VERSION 5.7 ;
  NOWIREEXTENSIONATPIN ON ;
  DIVIDERCHAR "/" ;
  BUSBITCHARS "[]" ;
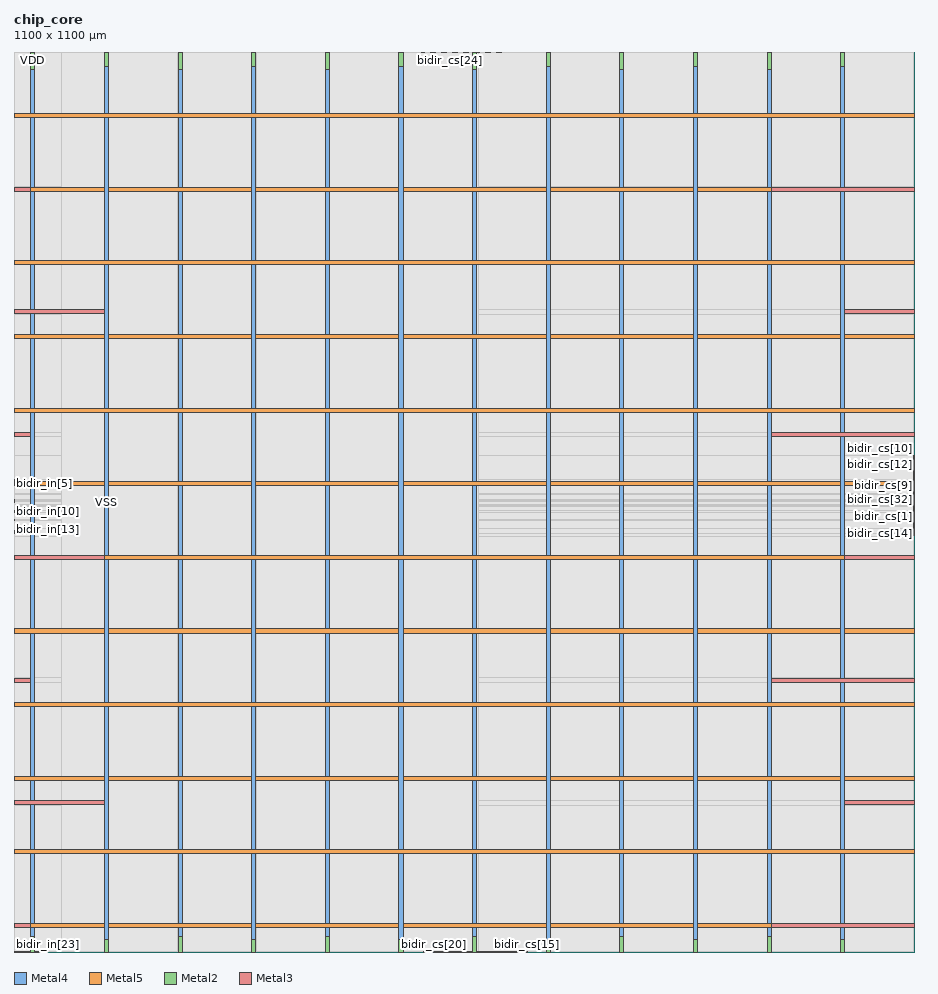
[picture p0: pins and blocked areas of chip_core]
MACRO chip_core
  CLASS BLOCK ;
  FOREIGN chip_core ;
  ORIGIN 0.000 0.000 ;
  SIZE 1100.000 BY 1100.000 ;
  PIN VDD
    DIRECTION INOUT ;
    USE POWER ;
    PORT
      LAYER Metal4 ;
        RECT 20.540 0.000 25.540 1100.000 ;
    END
    PORT
      LAYER Metal4 ;
        RECT 200.540 0.000 205.540 1100.000 ;
    END
    PORT
      LAYER Metal4 ;
        RECT 380.540 0.000 385.540 1100.000 ;
    END
    PORT
      LAYER Metal4 ;
        RECT 560.540 0.000 565.540 1100.000 ;
    END
    PORT
      LAYER Metal4 ;
        RECT 740.540 0.000 745.540 1100.000 ;
    END
    PORT
      LAYER Metal4 ;
        RECT 920.540 0.000 925.540 1100.000 ;
    END
    PORT
      LAYER Metal5 ;
        RECT 0.000 29.830 1100.000 34.830 ;
    END
    PORT
      LAYER Metal5 ;
        RECT 0.000 209.830 1100.000 214.830 ;
    END
    PORT
      LAYER Metal5 ;
        RECT 0.000 389.830 1100.000 394.830 ;
    END
    PORT
      LAYER Metal5 ;
        RECT 0.000 569.830 1100.000 574.830 ;
    END
    PORT
      LAYER Metal5 ;
        RECT 0.000 749.830 1100.000 754.830 ;
    END
    PORT
      LAYER Metal5 ;
        RECT 0.000 929.830 1100.000 934.830 ;
    END
    PORT
      LAYER Metal2 ;
        RECT 20.540 0.000 25.540 19.470 ;
    END
    PORT
      LAYER Metal2 ;
        RECT 20.540 1078.130 25.540 1100.000 ;
    END
    PORT
      LAYER Metal2 ;
        RECT 200.540 0.000 205.540 19.470 ;
    END
    PORT
      LAYER Metal2 ;
        RECT 200.540 1078.130 205.540 1100.000 ;
    END
    PORT
      LAYER Metal2 ;
        RECT 380.540 0.000 385.540 19.470 ;
    END
    PORT
      LAYER Metal2 ;
        RECT 380.540 1078.130 385.540 1100.000 ;
    END
    PORT
      LAYER Metal2 ;
        RECT 560.540 0.000 565.540 19.470 ;
    END
    PORT
      LAYER Metal2 ;
        RECT 560.540 1078.130 565.540 1100.000 ;
    END
    PORT
      LAYER Metal2 ;
        RECT 740.540 0.000 745.540 19.470 ;
    END
    PORT
      LAYER Metal2 ;
        RECT 740.540 1078.130 745.540 1100.000 ;
    END
    PORT
      LAYER Metal2 ;
        RECT 920.540 0.000 925.540 19.470 ;
    END
    PORT
      LAYER Metal2 ;
        RECT 920.540 1078.130 925.540 1100.000 ;
    END
    PORT
      LAYER Metal3 ;
        RECT 0.000 29.830 20.730 34.830 ;
    END
    PORT
      LAYER Metal3 ;
        RECT 925.350 29.830 1100.000 34.830 ;
    END
    PORT
      LAYER Metal3 ;
        RECT 0.000 329.830 20.730 334.830 ;
    END
    PORT
      LAYER Metal3 ;
        RECT 925.350 329.830 1100.000 334.830 ;
    END
    PORT
      LAYER Metal3 ;
        RECT 0.000 629.830 20.730 634.830 ;
    END
    PORT
      LAYER Metal3 ;
        RECT 925.350 629.830 1100.000 634.830 ;
    END
    PORT
      LAYER Metal3 ;
        RECT 0.000 929.830 20.730 934.830 ;
    END
    PORT
      LAYER Metal3 ;
        RECT 925.350 929.830 1100.000 934.830 ;
    END
  END VDD
  PIN VSS
    DIRECTION INOUT ;
    USE GROUND ;
    PORT
      LAYER Metal4 ;
        RECT 110.540 0.000 115.540 1100.000 ;
    END
    PORT
      LAYER Metal4 ;
        RECT 290.540 0.000 295.540 1100.000 ;
    END
    PORT
      LAYER Metal4 ;
        RECT 470.540 0.000 475.540 1100.000 ;
    END
    PORT
      LAYER Metal4 ;
        RECT 650.540 0.000 655.540 1100.000 ;
    END
    PORT
      LAYER Metal4 ;
        RECT 830.540 0.000 835.540 1100.000 ;
    END
    PORT
      LAYER Metal4 ;
        RECT 1010.540 0.000 1015.540 1100.000 ;
    END
    PORT
      LAYER Metal5 ;
        RECT 0.000 119.830 1100.000 124.830 ;
    END
    PORT
      LAYER Metal5 ;
        RECT 0.000 299.830 1100.000 304.830 ;
    END
    PORT
      LAYER Metal5 ;
        RECT 0.000 479.830 1100.000 484.830 ;
    END
    PORT
      LAYER Metal5 ;
        RECT 0.000 659.830 1100.000 664.830 ;
    END
    PORT
      LAYER Metal5 ;
        RECT 0.000 839.830 1100.000 844.830 ;
    END
    PORT
      LAYER Metal5 ;
        RECT 0.000 1019.830 1100.000 1024.830 ;
    END
    PORT
      LAYER Metal2 ;
        RECT 110.540 0.000 115.540 15.550 ;
    END
    PORT
      LAYER Metal2 ;
        RECT 110.540 1082.050 115.540 1100.000 ;
    END
    PORT
      LAYER Metal2 ;
        RECT 290.540 0.000 295.540 15.550 ;
    END
    PORT
      LAYER Metal2 ;
        RECT 290.540 1082.050 295.540 1100.000 ;
    END
    PORT
      LAYER Metal2 ;
        RECT 470.540 0.000 475.540 15.550 ;
    END
    PORT
      LAYER Metal2 ;
        RECT 470.540 1082.050 475.540 1100.000 ;
    END
    PORT
      LAYER Metal2 ;
        RECT 650.540 0.000 655.540 15.550 ;
    END
    PORT
      LAYER Metal2 ;
        RECT 650.540 1082.050 655.540 1100.000 ;
    END
    PORT
      LAYER Metal2 ;
        RECT 830.540 0.000 835.540 15.550 ;
    END
    PORT
      LAYER Metal2 ;
        RECT 830.540 1082.050 835.540 1100.000 ;
    END
    PORT
      LAYER Metal2 ;
        RECT 1010.540 0.000 1015.540 15.550 ;
    END
    PORT
      LAYER Metal2 ;
        RECT 1010.540 1082.050 1015.540 1100.000 ;
    END
    PORT
      LAYER Metal3 ;
        RECT 0.000 179.830 110.730 184.830 ;
    END
    PORT
      LAYER Metal3 ;
        RECT 1015.350 179.830 1100.000 184.830 ;
    END
    PORT
      LAYER Metal3 ;
        RECT 0.000 479.830 110.730 484.830 ;
    END
    PORT
      LAYER Metal3 ;
        RECT 1015.350 479.830 1100.000 484.830 ;
    END
    PORT
      LAYER Metal3 ;
        RECT 0.000 779.830 110.730 784.830 ;
    END
    PORT
      LAYER Metal3 ;
        RECT 1015.350 779.830 1100.000 784.830 ;
    END
  END VSS
  PIN bidir_cs[0]
    DIRECTION OUTPUT ;
    USE SIGNAL ;
    ANTENNADIFFAREA 0.360800 ;
    PORT
      LAYER Metal2 ;
        RECT 505.120 1099.440 505.680 1100.000 ;
    END
  END bidir_cs[0]
  PIN bidir_cs[10]
    DIRECTION OUTPUT ;
    USE SIGNAL ;
    ANTENNADIFFAREA 0.360800 ;
    PORT
      LAYER Metal3 ;
        RECT 1099.440 605.920 1100.000 606.480 ;
    END
  END bidir_cs[10]
  PIN bidir_cs[11]
    DIRECTION OUTPUT ;
    USE SIGNAL ;
    ANTENNADIFFAREA 0.360800 ;
    PORT
      LAYER Metal2 ;
        RECT 524.160 1099.440 524.720 1100.000 ;
    END
  END bidir_cs[11]
  PIN bidir_cs[12]
    DIRECTION OUTPUT ;
    USE SIGNAL ;
    ANTENNADIFFAREA 0.360800 ;
    PORT
      LAYER Metal3 ;
        RECT 1099.440 595.840 1100.000 596.400 ;
    END
  END bidir_cs[12]
  PIN bidir_cs[13]
    DIRECTION OUTPUT ;
    USE SIGNAL ;
    ANTENNADIFFAREA 0.360800 ;
    PORT
      LAYER Metal3 ;
        RECT 1099.440 508.480 1100.000 509.040 ;
    END
  END bidir_cs[13]
  PIN bidir_cs[14]
    DIRECTION OUTPUT ;
    USE SIGNAL ;
    ANTENNADIFFAREA 0.360800 ;
    PORT
      LAYER Metal3 ;
        RECT 1099.440 510.720 1100.000 511.280 ;
    END
  END bidir_cs[14]
  PIN bidir_cs[15]
    DIRECTION OUTPUT ;
    USE SIGNAL ;
    ANTENNADIFFAREA 0.360800 ;
    PORT
      LAYER Metal2 ;
        RECT 627.200 0.000 627.760 0.560 ;
    END
  END bidir_cs[15]
  PIN bidir_cs[16]
    DIRECTION OUTPUT ;
    USE SIGNAL ;
    ANTENNADIFFAREA 0.360800 ;
    PORT
      LAYER Metal2 ;
        RECT 500.640 0.000 501.200 0.560 ;
    END
  END bidir_cs[16]
  PIN bidir_cs[17]
    DIRECTION OUTPUT ;
    USE SIGNAL ;
    ANTENNADIFFAREA 0.360800 ;
    PORT
      LAYER Metal2 ;
        RECT 545.440 0.000 546.000 0.560 ;
    END
  END bidir_cs[17]
  PIN bidir_cs[18]
    DIRECTION OUTPUT ;
    USE SIGNAL ;
    ANTENNADIFFAREA 0.360800 ;
    PORT
      LAYER Metal3 ;
        RECT 1099.440 520.800 1100.000 521.360 ;
    END
  END bidir_cs[18]
  PIN bidir_cs[19]
    DIRECTION OUTPUT ;
    USE SIGNAL ;
    ANTENNADIFFAREA 0.360800 ;
    PORT
      LAYER Metal2 ;
        RECT 553.280 0.000 553.840 0.560 ;
    END
  END bidir_cs[19]
  PIN bidir_cs[1]
    DIRECTION OUTPUT ;
    USE SIGNAL ;
    ANTENNADIFFAREA 0.360800 ;
    PORT
      LAYER Metal3 ;
        RECT 1099.440 532.000 1100.000 532.560 ;
    END
  END bidir_cs[1]
  PIN bidir_cs[20]
    DIRECTION OUTPUT ;
    USE SIGNAL ;
    ANTENNADIFFAREA 0.360800 ;
    PORT
      LAYER Metal2 ;
        RECT 512.960 0.000 513.520 0.560 ;
    END
  END bidir_cs[20]
  PIN bidir_cs[21]
    DIRECTION OUTPUT ;
    USE SIGNAL ;
    ANTENNADIFFAREA 0.360800 ;
    PORT
      LAYER Metal2 ;
        RECT 524.160 0.000 524.720 0.560 ;
    END
  END bidir_cs[21]
  PIN bidir_cs[22]
    DIRECTION OUTPUT ;
    USE SIGNAL ;
    ANTENNADIFFAREA 0.360800 ;
    PORT
      LAYER Metal2 ;
        RECT 614.880 0.000 615.440 0.560 ;
    END
  END bidir_cs[22]
  PIN bidir_cs[23]
    DIRECTION OUTPUT ;
    USE SIGNAL ;
    ANTENNADIFFAREA 0.360800 ;
    PORT
      LAYER Metal2 ;
        RECT 605.920 0.000 606.480 0.560 ;
    END
  END bidir_cs[23]
  PIN bidir_cs[24]
    DIRECTION OUTPUT ;
    USE SIGNAL ;
    ANTENNADIFFAREA 0.360800 ;
    PORT
      LAYER Metal2 ;
        RECT 533.120 1099.440 533.680 1100.000 ;
    END
  END bidir_cs[24]
  PIN bidir_cs[25]
    DIRECTION OUTPUT ;
    USE SIGNAL ;
    ANTENNADIFFAREA 0.360800 ;
    PORT
      LAYER Metal3 ;
        RECT 1099.440 523.040 1100.000 523.600 ;
    END
  END bidir_cs[25]
  PIN bidir_cs[26]
    DIRECTION OUTPUT ;
    USE SIGNAL ;
    ANTENNADIFFAREA 0.360800 ;
    PORT
      LAYER Metal2 ;
        RECT 594.720 1099.440 595.280 1100.000 ;
    END
  END bidir_cs[26]
  PIN bidir_cs[27]
    DIRECTION OUTPUT ;
    USE SIGNAL ;
    ANTENNADIFFAREA 0.360800 ;
    PORT
      LAYER Metal2 ;
        RECT 549.920 1099.440 550.480 1100.000 ;
    END
  END bidir_cs[27]
  PIN bidir_cs[28]
    DIRECTION OUTPUT ;
    USE SIGNAL ;
    ANTENNADIFFAREA 0.360800 ;
    PORT
      LAYER Metal2 ;
        RECT 505.120 0.000 505.680 0.560 ;
    END
  END bidir_cs[28]
  PIN bidir_cs[29]
    DIRECTION OUTPUT ;
    USE SIGNAL ;
    ANTENNADIFFAREA 0.360800 ;
    PORT
      LAYER Metal3 ;
        RECT 1099.440 524.160 1100.000 524.720 ;
    END
  END bidir_cs[29]
  PIN bidir_cs[2]
    DIRECTION OUTPUT ;
    USE SIGNAL ;
    ANTENNADIFFAREA 0.360800 ;
    PORT
      LAYER Metal2 ;
        RECT 518.560 1099.440 519.120 1100.000 ;
    END
  END bidir_cs[2]
  PIN bidir_cs[30]
    DIRECTION OUTPUT ;
    USE SIGNAL ;
    ANTENNADIFFAREA 0.360800 ;
    PORT
      LAYER Metal3 ;
        RECT 1099.440 536.480 1100.000 537.040 ;
    END
  END bidir_cs[30]
  PIN bidir_cs[31]
    DIRECTION OUTPUT ;
    USE SIGNAL ;
    ANTENNADIFFAREA 0.360800 ;
    PORT
      LAYER Metal2 ;
        RECT 558.880 0.000 559.440 0.560 ;
    END
  END bidir_cs[31]
  PIN bidir_cs[32]
    DIRECTION OUTPUT ;
    USE SIGNAL ;
    ANTENNADIFFAREA 0.360800 ;
    PORT
      LAYER Metal3 ;
        RECT 1099.440 543.200 1100.000 543.760 ;
    END
  END bidir_cs[32]
  PIN bidir_cs[33]
    DIRECTION OUTPUT ;
    USE SIGNAL ;
    ANTENNADIFFAREA 0.360800 ;
    PORT
      LAYER Metal2 ;
        RECT 604.800 0.000 605.360 0.560 ;
    END
  END bidir_cs[33]
  PIN bidir_cs[34]
    DIRECTION OUTPUT ;
    USE SIGNAL ;
    ANTENNADIFFAREA 0.360800 ;
    PORT
      LAYER Metal2 ;
        RECT 570.080 1099.440 570.640 1100.000 ;
    END
  END bidir_cs[34]
  PIN bidir_cs[35]
    DIRECTION OUTPUT ;
    USE SIGNAL ;
    ANTENNADIFFAREA 0.360800 ;
    PORT
      LAYER Metal2 ;
        RECT 519.680 1099.440 520.240 1100.000 ;
    END
  END bidir_cs[35]
  PIN bidir_cs[36]
    DIRECTION OUTPUT ;
    USE SIGNAL ;
    ANTENNADIFFAREA 0.360800 ;
    PORT
      LAYER Metal3 ;
        RECT 1099.440 539.840 1100.000 540.400 ;
    END
  END bidir_cs[36]
  PIN bidir_cs[37]
    DIRECTION OUTPUT ;
    USE SIGNAL ;
    ANTENNADIFFAREA 0.360800 ;
    PORT
      LAYER Metal2 ;
        RECT 532.000 0.000 532.560 0.560 ;
    END
  END bidir_cs[37]
  PIN bidir_cs[38]
    DIRECTION OUTPUT ;
    USE SIGNAL ;
    ANTENNADIFFAREA 0.360800 ;
    PORT
      LAYER Metal2 ;
        RECT 571.200 0.000 571.760 0.560 ;
    END
  END bidir_cs[38]
  PIN bidir_cs[39]
    DIRECTION OUTPUT ;
    USE SIGNAL ;
    ANTENNADIFFAREA 0.360800 ;
    PORT
      LAYER Metal2 ;
        RECT 515.200 0.000 515.760 0.560 ;
    END
  END bidir_cs[39]
  PIN bidir_cs[3]
    DIRECTION OUTPUT ;
    USE SIGNAL ;
    ANTENNADIFFAREA 0.360800 ;
    PORT
      LAYER Metal3 ;
        RECT 1099.440 545.440 1100.000 546.000 ;
    END
  END bidir_cs[3]
  PIN bidir_cs[4]
    DIRECTION OUTPUT ;
    USE SIGNAL ;
    ANTENNADIFFAREA 0.360800 ;
    PORT
      LAYER Metal2 ;
        RECT 548.800 1099.440 549.360 1100.000 ;
    END
  END bidir_cs[4]
  PIN bidir_cs[5]
    DIRECTION OUTPUT ;
    USE SIGNAL ;
    ANTENNADIFFAREA 0.360800 ;
    PORT
      LAYER Metal2 ;
        RECT 590.240 1099.440 590.800 1100.000 ;
    END
  END bidir_cs[5]
  PIN bidir_cs[6]
    DIRECTION OUTPUT ;
    USE SIGNAL ;
    ANTENNADIFFAREA 0.360800 ;
    PORT
      LAYER Metal2 ;
        RECT 508.480 1099.440 509.040 1100.000 ;
    END
  END bidir_cs[6]
  PIN bidir_cs[7]
    DIRECTION OUTPUT ;
    USE SIGNAL ;
    ANTENNADIFFAREA 0.360800 ;
    PORT
      LAYER Metal3 ;
        RECT 1099.440 601.440 1100.000 602.000 ;
    END
  END bidir_cs[7]
  PIN bidir_cs[8]
    DIRECTION OUTPUT ;
    USE SIGNAL ;
    ANTENNADIFFAREA 0.360800 ;
    PORT
      LAYER Metal3 ;
        RECT 1099.440 526.400 1100.000 526.960 ;
    END
  END bidir_cs[8]
  PIN bidir_cs[9]
    DIRECTION OUTPUT ;
    USE SIGNAL ;
    ANTENNADIFFAREA 0.360800 ;
    PORT
      LAYER Metal3 ;
        RECT 1099.440 570.080 1100.000 570.640 ;
    END
  END bidir_cs[9]
  PIN bidir_ie[0]
    DIRECTION OUTPUT ;
    USE SIGNAL ;
    ANTENNADIFFAREA 0.360800 ;
    PORT
      LAYER Metal3 ;
        RECT 1099.440 527.520 1100.000 528.080 ;
    END
  END bidir_ie[0]
  PIN bidir_ie[10]
    DIRECTION OUTPUT ;
    USE SIGNAL ;
    ANTENNADIFFAREA 0.360800 ;
    PORT
      LAYER Metal3 ;
        RECT 1099.440 512.960 1100.000 513.520 ;
    END
  END bidir_ie[10]
  PIN bidir_ie[11]
    DIRECTION OUTPUT ;
    USE SIGNAL ;
    ANTENNADIFFAREA 0.360800 ;
    PORT
      LAYER Metal3 ;
        RECT 1099.440 546.560 1100.000 547.120 ;
    END
  END bidir_ie[11]
  PIN bidir_ie[12]
    DIRECTION OUTPUT ;
    USE SIGNAL ;
    ANTENNADIFFAREA 0.360800 ;
    PORT
      LAYER Metal3 ;
        RECT 1099.440 573.440 1100.000 574.000 ;
    END
  END bidir_ie[12]
  PIN bidir_ie[13]
    DIRECTION OUTPUT ;
    USE SIGNAL ;
    ANTENNADIFFAREA 0.360800 ;
    PORT
      LAYER Metal2 ;
        RECT 588.000 0.000 588.560 0.560 ;
    END
  END bidir_ie[13]
  PIN bidir_ie[14]
    DIRECTION OUTPUT ;
    USE SIGNAL ;
    ANTENNADIFFAREA 0.360800 ;
    PORT
      LAYER Metal3 ;
        RECT 1099.440 557.760 1100.000 558.320 ;
    END
  END bidir_ie[14]
  PIN bidir_ie[15]
    DIRECTION OUTPUT ;
    USE SIGNAL ;
    ANTENNADIFFAREA 0.360800 ;
    PORT
      LAYER Metal3 ;
        RECT 1099.440 592.480 1100.000 593.040 ;
    END
  END bidir_ie[15]
  PIN bidir_ie[16]
    DIRECTION OUTPUT ;
    USE SIGNAL ;
    ANTENNADIFFAREA 0.360800 ;
    PORT
      LAYER Metal2 ;
        RECT 624.960 0.000 625.520 0.560 ;
    END
  END bidir_ie[16]
  PIN bidir_ie[17]
    DIRECTION OUTPUT ;
    USE SIGNAL ;
    ANTENNADIFFAREA 0.360800 ;
    PORT
      LAYER Metal2 ;
        RECT 584.640 1099.440 585.200 1100.000 ;
    END
  END bidir_ie[17]
  PIN bidir_ie[18]
    DIRECTION OUTPUT ;
    USE SIGNAL ;
    ANTENNADIFFAREA 0.360800 ;
    PORT
      LAYER Metal2 ;
        RECT 511.840 1099.440 512.400 1100.000 ;
    END
  END bidir_ie[18]
  PIN bidir_ie[19]
    DIRECTION OUTPUT ;
    USE SIGNAL ;
    ANTENNADIFFAREA 0.360800 ;
    PORT
      LAYER Metal2 ;
        RECT 552.160 1099.440 552.720 1100.000 ;
    END
  END bidir_ie[19]
  PIN bidir_ie[1]
    DIRECTION OUTPUT ;
    USE SIGNAL ;
    ANTENNADIFFAREA 0.360800 ;
    PORT
      LAYER Metal3 ;
        RECT 1099.440 533.120 1100.000 533.680 ;
    END
  END bidir_ie[1]
  PIN bidir_ie[20]
    DIRECTION OUTPUT ;
    USE SIGNAL ;
    ANTENNADIFFAREA 0.360800 ;
    PORT
      LAYER Metal2 ;
        RECT 518.560 0.000 519.120 0.560 ;
    END
  END bidir_ie[20]
  PIN bidir_ie[21]
    DIRECTION OUTPUT ;
    USE SIGNAL ;
    ANTENNADIFFAREA 0.360800 ;
    PORT
      LAYER Metal2 ;
        RECT 499.520 1099.440 500.080 1100.000 ;
    END
  END bidir_ie[21]
  PIN bidir_ie[22]
    DIRECTION OUTPUT ;
    USE SIGNAL ;
    ANTENNADIFFAREA 0.360800 ;
    PORT
      LAYER Metal2 ;
        RECT 547.680 0.000 548.240 0.560 ;
    END
  END bidir_ie[22]
  PIN bidir_ie[23]
    DIRECTION OUTPUT ;
    USE SIGNAL ;
    ANTENNADIFFAREA 0.360800 ;
    PORT
      LAYER Metal3 ;
        RECT 1099.440 521.920 1100.000 522.480 ;
    END
  END bidir_ie[23]
  PIN bidir_ie[24]
    DIRECTION OUTPUT ;
    USE SIGNAL ;
    ANTENNADIFFAREA 0.360800 ;
    PORT
      LAYER Metal2 ;
        RECT 543.200 1099.440 543.760 1100.000 ;
    END
  END bidir_ie[24]
  PIN bidir_ie[25]
    DIRECTION OUTPUT ;
    USE SIGNAL ;
    ANTENNADIFFAREA 0.360800 ;
    PORT
      LAYER Metal2 ;
        RECT 493.920 1099.440 494.480 1100.000 ;
    END
  END bidir_ie[25]
  PIN bidir_ie[26]
    DIRECTION OUTPUT ;
    USE SIGNAL ;
    ANTENNADIFFAREA 0.360800 ;
    PORT
      LAYER Metal2 ;
        RECT 542.080 1099.440 542.640 1100.000 ;
    END
  END bidir_ie[26]
  PIN bidir_ie[27]
    DIRECTION OUTPUT ;
    USE SIGNAL ;
    ANTENNADIFFAREA 0.360800 ;
    PORT
      LAYER Metal2 ;
        RECT 539.840 1099.440 540.400 1100.000 ;
    END
  END bidir_ie[27]
  PIN bidir_ie[28]
    DIRECTION OUTPUT ;
    USE SIGNAL ;
    ANTENNADIFFAREA 0.360800 ;
    PORT
      LAYER Metal2 ;
        RECT 523.040 1099.440 523.600 1100.000 ;
    END
  END bidir_ie[28]
  PIN bidir_ie[29]
    DIRECTION OUTPUT ;
    USE SIGNAL ;
    ANTENNADIFFAREA 0.360800 ;
    PORT
      LAYER Metal2 ;
        RECT 523.040 0.000 523.600 0.560 ;
    END
  END bidir_ie[29]
  PIN bidir_ie[2]
    DIRECTION OUTPUT ;
    USE SIGNAL ;
    ANTENNADIFFAREA 0.360800 ;
    PORT
      LAYER Metal3 ;
        RECT 0.000 549.920 0.560 550.480 ;
    END
  END bidir_ie[2]
  PIN bidir_ie[30]
    DIRECTION OUTPUT ;
    USE SIGNAL ;
    ANTENNADIFFAREA 0.360800 ;
    PORT
      LAYER Metal2 ;
        RECT 556.640 0.000 557.200 0.560 ;
    END
  END bidir_ie[30]
  PIN bidir_ie[31]
    DIRECTION OUTPUT ;
    USE SIGNAL ;
    ANTENNADIFFAREA 0.360800 ;
    PORT
      LAYER Metal3 ;
        RECT 1099.440 553.280 1100.000 553.840 ;
    END
  END bidir_ie[31]
  PIN bidir_ie[32]
    DIRECTION OUTPUT ;
    USE SIGNAL ;
    ANTENNADIFFAREA 0.360800 ;
    PORT
      LAYER Metal3 ;
        RECT 1099.440 596.960 1100.000 597.520 ;
    END
  END bidir_ie[32]
  PIN bidir_ie[33]
    DIRECTION OUTPUT ;
    USE SIGNAL ;
    ANTENNADIFFAREA 0.360800 ;
    PORT
      LAYER Metal2 ;
        RECT 547.680 1099.440 548.240 1100.000 ;
    END
  END bidir_ie[33]
  PIN bidir_ie[34]
    DIRECTION OUTPUT ;
    USE SIGNAL ;
    ANTENNADIFFAREA 0.360800 ;
    PORT
      LAYER Metal2 ;
        RECT 556.640 1099.440 557.200 1100.000 ;
    END
  END bidir_ie[34]
  PIN bidir_ie[35]
    DIRECTION OUTPUT ;
    USE SIGNAL ;
    ANTENNADIFFAREA 0.360800 ;
    PORT
      LAYER Metal3 ;
        RECT 1099.440 554.400 1100.000 554.960 ;
    END
  END bidir_ie[35]
  PIN bidir_ie[36]
    DIRECTION OUTPUT ;
    USE SIGNAL ;
    ANTENNADIFFAREA 0.360800 ;
    PORT
      LAYER Metal2 ;
        RECT 551.040 0.000 551.600 0.560 ;
    END
  END bidir_ie[36]
  PIN bidir_ie[37]
    DIRECTION OUTPUT ;
    USE SIGNAL ;
    ANTENNADIFFAREA 0.360800 ;
    PORT
      LAYER Metal2 ;
        RECT 552.160 0.000 552.720 0.560 ;
    END
  END bidir_ie[37]
  PIN bidir_ie[38]
    DIRECTION OUTPUT ;
    USE SIGNAL ;
    ANTENNADIFFAREA 0.360800 ;
    PORT
      LAYER Metal2 ;
        RECT 584.640 0.000 585.200 0.560 ;
    END
  END bidir_ie[38]
  PIN bidir_ie[39]
    DIRECTION OUTPUT ;
    USE SIGNAL ;
    ANTENNADIFFAREA 0.360800 ;
    PORT
      LAYER Metal3 ;
        RECT 1099.440 511.840 1100.000 512.400 ;
    END
  END bidir_ie[39]
  PIN bidir_ie[3]
    DIRECTION OUTPUT ;
    USE SIGNAL ;
    ANTENNADIFFAREA 0.360800 ;
    PORT
      LAYER Metal2 ;
        RECT 618.240 0.000 618.800 0.560 ;
    END
  END bidir_ie[3]
  PIN bidir_ie[4]
    DIRECTION OUTPUT ;
    USE SIGNAL ;
    ANTENNADIFFAREA 0.360800 ;
    PORT
      LAYER Metal2 ;
        RECT 526.400 0.000 526.960 0.560 ;
    END
  END bidir_ie[4]
  PIN bidir_ie[5]
    DIRECTION OUTPUT ;
    USE SIGNAL ;
    ANTENNADIFFAREA 0.360800 ;
    PORT
      LAYER Metal2 ;
        RECT 608.160 0.000 608.720 0.560 ;
    END
  END bidir_ie[5]
  PIN bidir_ie[6]
    DIRECTION OUTPUT ;
    USE SIGNAL ;
    ANTENNADIFFAREA 0.360800 ;
    PORT
      LAYER Metal2 ;
        RECT 512.960 1099.440 513.520 1100.000 ;
    END
  END bidir_ie[6]
  PIN bidir_ie[7]
    DIRECTION OUTPUT ;
    USE SIGNAL ;
    ANTENNADIFFAREA 0.360800 ;
    PORT
      LAYER Metal3 ;
        RECT 0.000 548.800 0.560 549.360 ;
    END
  END bidir_ie[7]
  PIN bidir_ie[8]
    DIRECTION OUTPUT ;
    USE SIGNAL ;
    ANTENNADIFFAREA 0.360800 ;
    PORT
      LAYER Metal2 ;
        RECT 591.360 0.000 591.920 0.560 ;
    END
  END bidir_ie[8]
  PIN bidir_ie[9]
    DIRECTION OUTPUT ;
    USE SIGNAL ;
    ANTENNADIFFAREA 0.360800 ;
    PORT
      LAYER Metal2 ;
        RECT 567.840 0.000 568.400 0.560 ;
    END
  END bidir_ie[9]
  PIN bidir_in[0]
    DIRECTION INPUT ;
    USE SIGNAL ;
    ANTENNAGATEAREA 0.396000 ;
    ANTENNADIFFAREA 0.410400 ;
    PORT
      LAYER Metal3 ;
        RECT 0.000 575.680 0.560 576.240 ;
    END
  END bidir_in[0]
  PIN bidir_in[10]
    DIRECTION INPUT ;
    USE SIGNAL ;
    ANTENNAGATEAREA 0.396000 ;
    ANTENNADIFFAREA 0.410400 ;
    PORT
      LAYER Metal3 ;
        RECT 0.000 537.600 0.560 538.160 ;
    END
  END bidir_in[10]
  PIN bidir_in[11]
    DIRECTION INPUT ;
    USE SIGNAL ;
    ANTENNAGATEAREA 0.396000 ;
    ANTENNADIFFAREA 0.410400 ;
    PORT
      LAYER Metal3 ;
        RECT 0.000 538.720 0.560 539.280 ;
    END
  END bidir_in[11]
  PIN bidir_in[12]
    DIRECTION INPUT ;
    USE SIGNAL ;
    ANTENNAGATEAREA 0.396000 ;
    ANTENNADIFFAREA 0.410400 ;
    PORT
      LAYER Metal3 ;
        RECT 0.000 544.320 0.560 544.880 ;
    END
  END bidir_in[12]
  PIN bidir_in[13]
    DIRECTION INPUT ;
    USE SIGNAL ;
    ANTENNAGATEAREA 0.396000 ;
    ANTENNADIFFAREA 0.410400 ;
    PORT
      LAYER Metal3 ;
        RECT 0.000 516.320 0.560 516.880 ;
    END
  END bidir_in[13]
  PIN bidir_in[14]
    DIRECTION INPUT ;
    USE SIGNAL ;
    ANTENNAGATEAREA 0.396000 ;
    ANTENNADIFFAREA 0.410400 ;
    PORT
      LAYER Metal3 ;
        RECT 0.000 552.160 0.560 552.720 ;
    END
  END bidir_in[14]
  PIN bidir_in[15]
    DIRECTION INPUT ;
    USE SIGNAL ;
    ANTENNAGATEAREA 0.396000 ;
    ANTENNADIFFAREA 0.410400 ;
    PORT
      LAYER Metal3 ;
        RECT 0.000 527.520 0.560 528.080 ;
    END
  END bidir_in[15]
  PIN bidir_in[16]
    DIRECTION INPUT ;
    USE SIGNAL ;
    PORT
      LAYER Metal2 ;
        RECT 1.120 0.000 1.680 0.560 ;
    END
  END bidir_in[16]
  PIN bidir_in[17]
    DIRECTION INPUT ;
    USE SIGNAL ;
    PORT
      LAYER Metal2 ;
        RECT 2.240 0.000 2.800 0.560 ;
    END
  END bidir_in[17]
  PIN bidir_in[18]
    DIRECTION INPUT ;
    USE SIGNAL ;
    PORT
      LAYER Metal2 ;
        RECT 3.360 0.000 3.920 0.560 ;
    END
  END bidir_in[18]
  PIN bidir_in[19]
    DIRECTION INPUT ;
    USE SIGNAL ;
    PORT
      LAYER Metal2 ;
        RECT 4.480 0.000 5.040 0.560 ;
    END
  END bidir_in[19]
  PIN bidir_in[1]
    DIRECTION INPUT ;
    USE SIGNAL ;
    ANTENNAGATEAREA 0.396000 ;
    ANTENNADIFFAREA 0.410400 ;
    PORT
      LAYER Metal3 ;
        RECT 0.000 511.840 0.560 512.400 ;
    END
  END bidir_in[1]
  PIN bidir_in[20]
    DIRECTION INPUT ;
    USE SIGNAL ;
    PORT
      LAYER Metal2 ;
        RECT 5.600 0.000 6.160 0.560 ;
    END
  END bidir_in[20]
  PIN bidir_in[21]
    DIRECTION INPUT ;
    USE SIGNAL ;
    PORT
      LAYER Metal2 ;
        RECT 6.720 0.000 7.280 0.560 ;
    END
  END bidir_in[21]
  PIN bidir_in[22]
    DIRECTION INPUT ;
    USE SIGNAL ;
    PORT
      LAYER Metal2 ;
        RECT 7.840 0.000 8.400 0.560 ;
    END
  END bidir_in[22]
  PIN bidir_in[23]
    DIRECTION INPUT ;
    USE SIGNAL ;
    PORT
      LAYER Metal2 ;
        RECT 8.960 0.000 9.520 0.560 ;
    END
  END bidir_in[23]
  PIN bidir_in[24]
    DIRECTION INPUT ;
    USE SIGNAL ;
    PORT
      LAYER Metal2 ;
        RECT 10.080 0.000 10.640 0.560 ;
    END
  END bidir_in[24]
  PIN bidir_in[25]
    DIRECTION INPUT ;
    USE SIGNAL ;
    PORT
      LAYER Metal2 ;
        RECT 11.200 0.000 11.760 0.560 ;
    END
  END bidir_in[25]
  PIN bidir_in[26]
    DIRECTION INPUT ;
    USE SIGNAL ;
    PORT
      LAYER Metal2 ;
        RECT 12.320 0.000 12.880 0.560 ;
    END
  END bidir_in[26]
  PIN bidir_in[27]
    DIRECTION INPUT ;
    USE SIGNAL ;
    PORT
      LAYER Metal2 ;
        RECT 13.440 0.000 14.000 0.560 ;
    END
  END bidir_in[27]
  PIN bidir_in[28]
    DIRECTION INPUT ;
    USE SIGNAL ;
    PORT
      LAYER Metal2 ;
        RECT 14.560 0.000 15.120 0.560 ;
    END
  END bidir_in[28]
  PIN bidir_in[29]
    DIRECTION INPUT ;
    USE SIGNAL ;
    PORT
      LAYER Metal2 ;
        RECT 15.680 0.000 16.240 0.560 ;
    END
  END bidir_in[29]
  PIN bidir_in[2]
    DIRECTION INPUT ;
    USE SIGNAL ;
    ANTENNAGATEAREA 0.396000 ;
    ANTENNADIFFAREA 0.410400 ;
    PORT
      LAYER Metal3 ;
        RECT 0.000 574.560 0.560 575.120 ;
    END
  END bidir_in[2]
  PIN bidir_in[30]
    DIRECTION INPUT ;
    USE SIGNAL ;
    PORT
      LAYER Metal2 ;
        RECT 16.800 0.000 17.360 0.560 ;
    END
  END bidir_in[30]
  PIN bidir_in[31]
    DIRECTION INPUT ;
    USE SIGNAL ;
    PORT
      LAYER Metal2 ;
        RECT 17.920 0.000 18.480 0.560 ;
    END
  END bidir_in[31]
  PIN bidir_in[32]
    DIRECTION INPUT ;
    USE SIGNAL ;
    PORT
      LAYER Metal2 ;
        RECT 19.040 0.000 19.600 0.560 ;
    END
  END bidir_in[32]
  PIN bidir_in[33]
    DIRECTION INPUT ;
    USE SIGNAL ;
    PORT
      LAYER Metal2 ;
        RECT 20.160 0.000 20.720 0.560 ;
    END
  END bidir_in[33]
  PIN bidir_in[34]
    DIRECTION INPUT ;
    USE SIGNAL ;
    PORT
      LAYER Metal2 ;
        RECT 25.760 0.000 26.320 0.560 ;
    END
  END bidir_in[34]
  PIN bidir_in[35]
    DIRECTION INPUT ;
    USE SIGNAL ;
    PORT
      LAYER Metal2 ;
        RECT 26.880 0.000 27.440 0.560 ;
    END
  END bidir_in[35]
  PIN bidir_in[36]
    DIRECTION INPUT ;
    USE SIGNAL ;
    PORT
      LAYER Metal2 ;
        RECT 28.000 0.000 28.560 0.560 ;
    END
  END bidir_in[36]
  PIN bidir_in[37]
    DIRECTION INPUT ;
    USE SIGNAL ;
    PORT
      LAYER Metal2 ;
        RECT 29.120 0.000 29.680 0.560 ;
    END
  END bidir_in[37]
  PIN bidir_in[38]
    DIRECTION INPUT ;
    USE SIGNAL ;
    PORT
      LAYER Metal2 ;
        RECT 30.240 0.000 30.800 0.560 ;
    END
  END bidir_in[38]
  PIN bidir_in[39]
    DIRECTION INPUT ;
    USE SIGNAL ;
    PORT
      LAYER Metal2 ;
        RECT 31.360 0.000 31.920 0.560 ;
    END
  END bidir_in[39]
  PIN bidir_in[3]
    DIRECTION INPUT ;
    USE SIGNAL ;
    ANTENNAGATEAREA 0.396000 ;
    ANTENNADIFFAREA 0.410400 ;
    PORT
      LAYER Metal3 ;
        RECT 0.000 558.880 0.560 559.440 ;
    END
  END bidir_in[3]
  PIN bidir_in[4]
    DIRECTION INPUT ;
    USE SIGNAL ;
    ANTENNAGATEAREA 0.396000 ;
    ANTENNADIFFAREA 0.410400 ;
    PORT
      LAYER Metal3 ;
        RECT 0.000 515.200 0.560 515.760 ;
    END
  END bidir_in[4]
  PIN bidir_in[5]
    DIRECTION INPUT ;
    USE SIGNAL ;
    ANTENNAGATEAREA 0.396000 ;
    ANTENNADIFFAREA 0.410400 ;
    PORT
      LAYER Metal3 ;
        RECT 0.000 572.320 0.560 572.880 ;
    END
  END bidir_in[5]
  PIN bidir_in[6]
    DIRECTION INPUT ;
    USE SIGNAL ;
    ANTENNAGATEAREA 0.396000 ;
    ANTENNADIFFAREA 0.410400 ;
    PORT
      LAYER Metal3 ;
        RECT 0.000 512.960 0.560 513.520 ;
    END
  END bidir_in[6]
  PIN bidir_in[7]
    DIRECTION INPUT ;
    USE SIGNAL ;
    ANTENNAGATEAREA 0.396000 ;
    ANTENNADIFFAREA 0.410400 ;
    PORT
      LAYER Metal3 ;
        RECT 0.000 573.440 0.560 574.000 ;
    END
  END bidir_in[7]
  PIN bidir_in[8]
    DIRECTION INPUT ;
    USE SIGNAL ;
    ANTENNAGATEAREA 0.396000 ;
    ANTENNADIFFAREA 0.410400 ;
    PORT
      LAYER Metal3 ;
        RECT 0.000 514.080 0.560 514.640 ;
    END
  END bidir_in[8]
  PIN bidir_in[9]
    DIRECTION INPUT ;
    USE SIGNAL ;
    ANTENNAGATEAREA 0.396000 ;
    ANTENNADIFFAREA 0.410400 ;
    PORT
      LAYER Metal3 ;
        RECT 0.000 560.000 0.560 560.560 ;
    END
  END bidir_in[9]
  PIN bidir_oe[0]
    DIRECTION OUTPUT ;
    USE SIGNAL ;
    ANTENNADIFFAREA 0.360800 ;
    PORT
      LAYER Metal2 ;
        RECT 546.560 0.000 547.120 0.560 ;
    END
  END bidir_oe[0]
  PIN bidir_oe[10]
    DIRECTION OUTPUT ;
    USE SIGNAL ;
    ANTENNADIFFAREA 0.360800 ;
    PORT
      LAYER Metal2 ;
        RECT 517.440 1099.440 518.000 1100.000 ;
    END
  END bidir_oe[10]
  PIN bidir_oe[11]
    DIRECTION OUTPUT ;
    USE SIGNAL ;
    ANTENNADIFFAREA 0.360800 ;
    PORT
      LAYER Metal2 ;
        RECT 533.120 0.000 533.680 0.560 ;
    END
  END bidir_oe[11]
  PIN bidir_oe[12]
    DIRECTION OUTPUT ;
    USE SIGNAL ;
    ANTENNADIFFAREA 0.360800 ;
    PORT
      LAYER Metal3 ;
        RECT 1099.440 537.600 1100.000 538.160 ;
    END
  END bidir_oe[12]
  PIN bidir_oe[13]
    DIRECTION OUTPUT ;
    USE SIGNAL ;
    ANTENNADIFFAREA 0.360800 ;
    PORT
      LAYER Metal2 ;
        RECT 570.080 0.000 570.640 0.560 ;
    END
  END bidir_oe[13]
  PIN bidir_oe[14]
    DIRECTION OUTPUT ;
    USE SIGNAL ;
    ANTENNADIFFAREA 0.360800 ;
    PORT
      LAYER Metal2 ;
        RECT 544.320 1099.440 544.880 1100.000 ;
    END
  END bidir_oe[14]
  PIN bidir_oe[15]
    DIRECTION OUTPUT ;
    USE SIGNAL ;
    ANTENNADIFFAREA 0.360800 ;
    PORT
      LAYER Metal3 ;
        RECT 1099.440 562.240 1100.000 562.800 ;
    END
  END bidir_oe[15]
  PIN bidir_oe[16]
    DIRECTION OUTPUT ;
    USE SIGNAL ;
    ANTENNADIFFAREA 0.536800 ;
    PORT
      LAYER Metal3 ;
        RECT 1099.440 519.680 1100.000 520.240 ;
    END
  END bidir_oe[16]
  PIN bidir_oe[17]
    DIRECTION OUTPUT ;
    USE SIGNAL ;
    ANTENNADIFFAREA 0.536800 ;
    PORT
      LAYER Metal3 ;
        RECT 1099.440 565.600 1100.000 566.160 ;
    END
  END bidir_oe[17]
  PIN bidir_oe[18]
    DIRECTION OUTPUT ;
    USE SIGNAL ;
    ANTENNADIFFAREA 0.536800 ;
    PORT
      LAYER Metal2 ;
        RECT 600.320 0.000 600.880 0.560 ;
    END
  END bidir_oe[18]
  PIN bidir_oe[19]
    DIRECTION OUTPUT ;
    USE SIGNAL ;
    ANTENNADIFFAREA 0.536800 ;
    PORT
      LAYER Metal2 ;
        RECT 594.720 0.000 595.280 0.560 ;
    END
  END bidir_oe[19]
  PIN bidir_oe[1]
    DIRECTION OUTPUT ;
    USE SIGNAL ;
    ANTENNADIFFAREA 0.360800 ;
    PORT
      LAYER Metal3 ;
        RECT 1099.440 572.320 1100.000 572.880 ;
    END
  END bidir_oe[1]
  PIN bidir_oe[20]
    DIRECTION OUTPUT ;
    USE SIGNAL ;
    ANTENNADIFFAREA 0.536800 ;
    PORT
      LAYER Metal2 ;
        RECT 520.800 0.000 521.360 0.560 ;
    END
  END bidir_oe[20]
  PIN bidir_oe[21]
    DIRECTION OUTPUT ;
    USE SIGNAL ;
    ANTENNADIFFAREA 0.536800 ;
    PORT
      LAYER Metal2 ;
        RECT 530.880 1099.440 531.440 1100.000 ;
    END
  END bidir_oe[21]
  PIN bidir_oe[22]
    DIRECTION OUTPUT ;
    USE SIGNAL ;
    ANTENNADIFFAREA 0.536800 ;
    PORT
      LAYER Metal2 ;
        RECT 536.480 0.000 537.040 0.560 ;
    END
  END bidir_oe[22]
  PIN bidir_oe[23]
    DIRECTION OUTPUT ;
    USE SIGNAL ;
    ANTENNADIFFAREA 0.536800 ;
    PORT
      LAYER Metal3 ;
        RECT 1099.440 564.480 1100.000 565.040 ;
    END
  END bidir_oe[23]
  PIN bidir_oe[24]
    DIRECTION OUTPUT ;
    USE SIGNAL ;
    ANTENNADIFFAREA 0.536800 ;
    PORT
      LAYER Metal2 ;
        RECT 509.600 0.000 510.160 0.560 ;
    END
  END bidir_oe[24]
  PIN bidir_oe[25]
    DIRECTION OUTPUT ;
    USE SIGNAL ;
    ANTENNADIFFAREA 0.536800 ;
    PORT
      LAYER Metal2 ;
        RECT 592.480 1099.440 593.040 1100.000 ;
    END
  END bidir_oe[25]
  PIN bidir_oe[26]
    DIRECTION OUTPUT ;
    USE SIGNAL ;
    ANTENNADIFFAREA 0.536800 ;
    PORT
      LAYER Metal2 ;
        RECT 511.840 0.000 512.400 0.560 ;
    END
  END bidir_oe[26]
  PIN bidir_oe[27]
    DIRECTION OUTPUT ;
    USE SIGNAL ;
    ANTENNADIFFAREA 0.536800 ;
    PORT
      LAYER Metal2 ;
        RECT 514.080 0.000 514.640 0.560 ;
    END
  END bidir_oe[27]
  PIN bidir_oe[28]
    DIRECTION OUTPUT ;
    USE SIGNAL ;
    ANTENNADIFFAREA 0.536800 ;
    PORT
      LAYER Metal2 ;
        RECT 582.400 0.000 582.960 0.560 ;
    END
  END bidir_oe[28]
  PIN bidir_oe[29]
    DIRECTION OUTPUT ;
    USE SIGNAL ;
    ANTENNADIFFAREA 0.536800 ;
    PORT
      LAYER Metal2 ;
        RECT 585.760 1099.440 586.320 1100.000 ;
    END
  END bidir_oe[29]
  PIN bidir_oe[2]
    DIRECTION OUTPUT ;
    USE SIGNAL ;
    ANTENNADIFFAREA 0.360800 ;
    PORT
      LAYER Metal3 ;
        RECT 1099.440 540.960 1100.000 541.520 ;
    END
  END bidir_oe[2]
  PIN bidir_oe[30]
    DIRECTION OUTPUT ;
    USE SIGNAL ;
    ANTENNADIFFAREA 0.536800 ;
    PORT
      LAYER Metal2 ;
        RECT 576.800 1099.440 577.360 1100.000 ;
    END
  END bidir_oe[30]
  PIN bidir_oe[31]
    DIRECTION OUTPUT ;
    USE SIGNAL ;
    ANTENNADIFFAREA 0.536800 ;
    PORT
      LAYER Metal2 ;
        RECT 510.720 1099.440 511.280 1100.000 ;
    END
  END bidir_oe[31]
  PIN bidir_oe[32]
    DIRECTION OUTPUT ;
    USE SIGNAL ;
    ANTENNADIFFAREA 0.536800 ;
    PORT
      LAYER Metal2 ;
        RECT 506.240 0.000 506.800 0.560 ;
    END
  END bidir_oe[32]
  PIN bidir_oe[33]
    DIRECTION OUTPUT ;
    USE SIGNAL ;
    ANTENNADIFFAREA 0.536800 ;
    PORT
      LAYER Metal2 ;
        RECT 554.400 0.000 554.960 0.560 ;
    END
  END bidir_oe[33]
  PIN bidir_oe[34]
    DIRECTION OUTPUT ;
    USE SIGNAL ;
    ANTENNADIFFAREA 0.536800 ;
    PORT
      LAYER Metal2 ;
        RECT 530.880 0.000 531.440 0.560 ;
    END
  END bidir_oe[34]
  PIN bidir_oe[35]
    DIRECTION OUTPUT ;
    USE SIGNAL ;
    ANTENNADIFFAREA 0.536800 ;
    PORT
      LAYER Metal2 ;
        RECT 575.680 0.000 576.240 0.560 ;
    END
  END bidir_oe[35]
  PIN bidir_oe[36]
    DIRECTION OUTPUT ;
    USE SIGNAL ;
    ANTENNADIFFAREA 0.536800 ;
    PORT
      LAYER Metal2 ;
        RECT 498.400 1099.440 498.960 1100.000 ;
    END
  END bidir_oe[36]
  PIN bidir_oe[37]
    DIRECTION OUTPUT ;
    USE SIGNAL ;
    ANTENNADIFFAREA 0.536800 ;
    PORT
      LAYER Metal2 ;
        RECT 577.920 1099.440 578.480 1100.000 ;
    END
  END bidir_oe[37]
  PIN bidir_oe[38]
    DIRECTION OUTPUT ;
    USE SIGNAL ;
    ANTENNADIFFAREA 0.536800 ;
    PORT
      LAYER Metal2 ;
        RECT 508.480 0.000 509.040 0.560 ;
    END
  END bidir_oe[38]
  PIN bidir_oe[39]
    DIRECTION OUTPUT ;
    USE SIGNAL ;
    ANTENNADIFFAREA 0.536800 ;
    PORT
      LAYER Metal2 ;
        RECT 527.520 0.000 528.080 0.560 ;
    END
  END bidir_oe[39]
  PIN bidir_oe[3]
    DIRECTION OUTPUT ;
    USE SIGNAL ;
    ANTENNADIFFAREA 0.360800 ;
    PORT
      LAYER Metal2 ;
        RECT 613.760 0.000 614.320 0.560 ;
    END
  END bidir_oe[3]
  PIN bidir_oe[4]
    DIRECTION OUTPUT ;
    USE SIGNAL ;
    ANTENNADIFFAREA 0.360800 ;
    PORT
      LAYER Metal2 ;
        RECT 581.280 0.000 581.840 0.560 ;
    END
  END bidir_oe[4]
  PIN bidir_oe[5]
    DIRECTION OUTPUT ;
    USE SIGNAL ;
    ANTENNADIFFAREA 0.360800 ;
    PORT
      LAYER Metal2 ;
        RECT 507.360 0.000 507.920 0.560 ;
    END
  END bidir_oe[5]
  PIN bidir_oe[6]
    DIRECTION OUTPUT ;
    USE SIGNAL ;
    ANTENNADIFFAREA 0.360800 ;
    PORT
      LAYER Metal2 ;
        RECT 538.720 1099.440 539.280 1100.000 ;
    END
  END bidir_oe[6]
  PIN bidir_oe[7]
    DIRECTION OUTPUT ;
    USE SIGNAL ;
    ANTENNADIFFAREA 0.360800 ;
    PORT
      LAYER Metal2 ;
        RECT 580.160 1099.440 580.720 1100.000 ;
    END
  END bidir_oe[7]
  PIN bidir_oe[8]
    DIRECTION OUTPUT ;
    USE SIGNAL ;
    ANTENNADIFFAREA 0.360800 ;
    PORT
      LAYER Metal2 ;
        RECT 535.360 0.000 535.920 0.560 ;
    END
  END bidir_oe[8]
  PIN bidir_oe[9]
    DIRECTION OUTPUT ;
    USE SIGNAL ;
    ANTENNADIFFAREA 0.360800 ;
    PORT
      LAYER Metal3 ;
        RECT 1099.440 571.200 1100.000 571.760 ;
    END
  END bidir_oe[9]
  PIN bidir_out[0]
    DIRECTION OUTPUT ;
    USE SIGNAL ;
    ANTENNADIFFAREA 0.360800 ;
    PORT
      LAYER Metal2 ;
        RECT 589.120 1099.440 589.680 1100.000 ;
    END
  END bidir_out[0]
  PIN bidir_out[10]
    DIRECTION OUTPUT ;
    USE SIGNAL ;
    ANTENNADIFFAREA 0.360800 ;
    PORT
      LAYER Metal2 ;
        RECT 565.600 1099.440 566.160 1100.000 ;
    END
  END bidir_out[10]
  PIN bidir_out[11]
    DIRECTION OUTPUT ;
    USE SIGNAL ;
    ANTENNADIFFAREA 0.360800 ;
    PORT
      LAYER Metal3 ;
        RECT 1099.440 555.520 1100.000 556.080 ;
    END
  END bidir_out[11]
  PIN bidir_out[12]
    DIRECTION OUTPUT ;
    USE SIGNAL ;
    ANTENNADIFFAREA 0.360800 ;
    PORT
      LAYER Metal2 ;
        RECT 540.960 0.000 541.520 0.560 ;
    END
  END bidir_out[12]
  PIN bidir_out[13]
    DIRECTION OUTPUT ;
    USE SIGNAL ;
    ANTENNADIFFAREA 0.360800 ;
    PORT
      LAYER Metal2 ;
        RECT 555.520 1099.440 556.080 1100.000 ;
    END
  END bidir_out[13]
  PIN bidir_out[14]
    DIRECTION OUTPUT ;
    USE SIGNAL ;
    ANTENNADIFFAREA 0.360800 ;
    PORT
      LAYER Metal3 ;
        RECT 1099.440 529.760 1100.000 530.320 ;
    END
  END bidir_out[14]
  PIN bidir_out[15]
    DIRECTION OUTPUT ;
    USE SIGNAL ;
    ANTENNADIFFAREA 0.360800 ;
    PORT
      LAYER Metal2 ;
        RECT 551.040 1099.440 551.600 1100.000 ;
    END
  END bidir_out[15]
  PIN bidir_out[16]
    DIRECTION OUTPUT ;
    USE SIGNAL ;
    ANTENNADIFFAREA 0.536800 ;
    PORT
      LAYER Metal3 ;
        RECT 1099.440 581.280 1100.000 581.840 ;
    END
  END bidir_out[16]
  PIN bidir_out[17]
    DIRECTION OUTPUT ;
    USE SIGNAL ;
    ANTENNADIFFAREA 0.360800 ;
    PORT
      LAYER Metal2 ;
        RECT 576.800 0.000 577.360 0.560 ;
    END
  END bidir_out[17]
  PIN bidir_out[18]
    DIRECTION OUTPUT ;
    USE SIGNAL ;
    ANTENNADIFFAREA 0.360800 ;
    PORT
      LAYER Metal3 ;
        RECT 1099.440 534.240 1100.000 534.800 ;
    END
  END bidir_out[18]
  PIN bidir_out[19]
    DIRECTION OUTPUT ;
    USE SIGNAL ;
    ANTENNADIFFAREA 0.360800 ;
    PORT
      LAYER Metal2 ;
        RECT 539.840 0.000 540.400 0.560 ;
    END
  END bidir_out[19]
  PIN bidir_out[1]
    DIRECTION OUTPUT ;
    USE SIGNAL ;
    ANTENNADIFFAREA 0.360800 ;
    PORT
      LAYER Metal2 ;
        RECT 566.720 1099.440 567.280 1100.000 ;
    END
  END bidir_out[1]
  PIN bidir_out[20]
    DIRECTION OUTPUT ;
    USE SIGNAL ;
    ANTENNADIFFAREA 0.360800 ;
    PORT
      LAYER Metal2 ;
        RECT 554.400 1099.440 554.960 1100.000 ;
    END
  END bidir_out[20]
  PIN bidir_out[21]
    DIRECTION OUTPUT ;
    USE SIGNAL ;
    ANTENNADIFFAREA 0.360800 ;
    PORT
      LAYER Metal2 ;
        RECT 535.360 1099.440 535.920 1100.000 ;
    END
  END bidir_out[21]
  PIN bidir_out[22]
    DIRECTION OUTPUT ;
    USE SIGNAL ;
    ANTENNADIFFAREA 0.360800 ;
    PORT
      LAYER Metal2 ;
        RECT 593.600 1099.440 594.160 1100.000 ;
    END
  END bidir_out[22]
  PIN bidir_out[23]
    DIRECTION OUTPUT ;
    USE SIGNAL ;
    ANTENNADIFFAREA 0.360800 ;
    PORT
      LAYER Metal3 ;
        RECT 1099.440 547.680 1100.000 548.240 ;
    END
  END bidir_out[23]
  PIN bidir_out[24]
    DIRECTION OUTPUT ;
    USE SIGNAL ;
    ANTENNADIFFAREA 0.360800 ;
    PORT
      LAYER Metal2 ;
        RECT 540.960 1099.440 541.520 1100.000 ;
    END
  END bidir_out[24]
  PIN bidir_out[25]
    DIRECTION OUTPUT ;
    USE SIGNAL ;
    ANTENNADIFFAREA 0.360800 ;
    PORT
      LAYER Metal2 ;
        RECT 521.920 0.000 522.480 0.560 ;
    END
  END bidir_out[25]
  PIN bidir_out[26]
    DIRECTION OUTPUT ;
    USE SIGNAL ;
    ANTENNADIFFAREA 0.360800 ;
    PORT
      LAYER Metal3 ;
        RECT 1099.440 600.320 1100.000 600.880 ;
    END
  END bidir_out[26]
  PIN bidir_out[27]
    DIRECTION OUTPUT ;
    USE SIGNAL ;
    ANTENNADIFFAREA 0.360800 ;
    PORT
      LAYER Metal2 ;
        RECT 616.000 0.000 616.560 0.560 ;
    END
  END bidir_out[27]
  PIN bidir_out[28]
    DIRECTION OUTPUT ;
    USE SIGNAL ;
    ANTENNADIFFAREA 0.360800 ;
    PORT
      LAYER Metal2 ;
        RECT 517.440 0.000 518.000 0.560 ;
    END
  END bidir_out[28]
  PIN bidir_out[29]
    DIRECTION OUTPUT ;
    USE SIGNAL ;
    ANTENNADIFFAREA 0.360800 ;
    PORT
      LAYER Metal2 ;
        RECT 537.600 1099.440 538.160 1100.000 ;
    END
  END bidir_out[29]
  PIN bidir_out[2]
    DIRECTION OUTPUT ;
    USE SIGNAL ;
    ANTENNADIFFAREA 0.360800 ;
    PORT
      LAYER Metal2 ;
        RECT 507.360 1099.440 507.920 1100.000 ;
    END
  END bidir_out[2]
  PIN bidir_out[30]
    DIRECTION OUTPUT ;
    USE SIGNAL ;
    ANTENNADIFFAREA 0.360800 ;
    PORT
      LAYER Metal3 ;
        RECT 0.000 547.680 0.560 548.240 ;
    END
  END bidir_out[30]
  PIN bidir_out[31]
    DIRECTION OUTPUT ;
    USE SIGNAL ;
    ANTENNADIFFAREA 0.360800 ;
    PORT
      LAYER Metal3 ;
        RECT 1099.440 509.600 1100.000 510.160 ;
    END
  END bidir_out[31]
  PIN bidir_out[32]
    DIRECTION OUTPUT ;
    USE SIGNAL ;
    ANTENNADIFFAREA 0.360800 ;
    PORT
      LAYER Metal2 ;
        RECT 585.760 0.000 586.320 0.560 ;
    END
  END bidir_out[32]
  PIN bidir_out[33]
    DIRECTION OUTPUT ;
    USE SIGNAL ;
    ANTENNADIFFAREA 0.360800 ;
    PORT
      LAYER Metal2 ;
        RECT 619.360 0.000 619.920 0.560 ;
    END
  END bidir_out[33]
  PIN bidir_out[34]
    DIRECTION OUTPUT ;
    USE SIGNAL ;
    ANTENNADIFFAREA 0.360800 ;
    PORT
      LAYER Metal3 ;
        RECT 1099.440 590.240 1100.000 590.800 ;
    END
  END bidir_out[34]
  PIN bidir_out[35]
    DIRECTION OUTPUT ;
    USE SIGNAL ;
    ANTENNADIFFAREA 0.360800 ;
    PORT
      LAYER Metal2 ;
        RECT 621.600 0.000 622.160 0.560 ;
    END
  END bidir_out[35]
  PIN bidir_out[36]
    DIRECTION OUTPUT ;
    USE SIGNAL ;
    ANTENNADIFFAREA 0.360800 ;
    PORT
      LAYER Metal2 ;
        RECT 596.960 0.000 597.520 0.560 ;
    END
  END bidir_out[36]
  PIN bidir_out[37]
    DIRECTION OUTPUT ;
    USE SIGNAL ;
    ANTENNADIFFAREA 0.360800 ;
    PORT
      LAYER Metal2 ;
        RECT 492.800 1099.440 493.360 1100.000 ;
    END
  END bidir_out[37]
  PIN bidir_out[38]
    DIRECTION OUTPUT ;
    USE SIGNAL ;
    ANTENNADIFFAREA 0.360800 ;
    PORT
      LAYER Metal3 ;
        RECT 1099.440 552.160 1100.000 552.720 ;
    END
  END bidir_out[38]
  PIN bidir_out[39]
    DIRECTION OUTPUT ;
    USE SIGNAL ;
    ANTENNADIFFAREA 0.360800 ;
    PORT
      LAYER Metal3 ;
        RECT 1099.440 579.040 1100.000 579.600 ;
    END
  END bidir_out[39]
  PIN bidir_out[3]
    DIRECTION OUTPUT ;
    USE SIGNAL ;
    ANTENNADIFFAREA 0.360800 ;
    PORT
      LAYER Metal2 ;
        RECT 620.480 0.000 621.040 0.560 ;
    END
  END bidir_out[3]
  PIN bidir_out[4]
    DIRECTION OUTPUT ;
    USE SIGNAL ;
    ANTENNADIFFAREA 0.360800 ;
    PORT
      LAYER Metal3 ;
        RECT 1099.440 551.040 1100.000 551.600 ;
    END
  END bidir_out[4]
  PIN bidir_out[5]
    DIRECTION OUTPUT ;
    USE SIGNAL ;
    ANTENNADIFFAREA 0.360800 ;
    PORT
      LAYER Metal2 ;
        RECT 601.440 0.000 602.000 0.560 ;
    END
  END bidir_out[5]
  PIN bidir_out[6]
    DIRECTION OUTPUT ;
    USE SIGNAL ;
    ANTENNADIFFAREA 0.360800 ;
    PORT
      LAYER Metal3 ;
        RECT 1099.440 594.720 1100.000 595.280 ;
    END
  END bidir_out[6]
  PIN bidir_out[7]
    DIRECTION OUTPUT ;
    USE SIGNAL ;
    ANTENNADIFFAREA 0.360800 ;
    PORT
      LAYER Metal2 ;
        RECT 586.880 1099.440 587.440 1100.000 ;
    END
  END bidir_out[7]
  PIN bidir_out[8]
    DIRECTION OUTPUT ;
    USE SIGNAL ;
    ANTENNADIFFAREA 0.360800 ;
    PORT
      LAYER Metal3 ;
        RECT 1099.440 517.440 1100.000 518.000 ;
    END
  END bidir_out[8]
  PIN bidir_out[9]
    DIRECTION OUTPUT ;
    USE SIGNAL ;
    ANTENNADIFFAREA 0.360800 ;
    PORT
      LAYER Metal3 ;
        RECT 1099.440 560.000 1100.000 560.560 ;
    END
  END bidir_out[9]
  PIN bidir_pd[0]
    DIRECTION OUTPUT ;
    USE SIGNAL ;
    ANTENNADIFFAREA 0.360800 ;
    PORT
      LAYER Metal2 ;
        RECT 572.320 1099.440 572.880 1100.000 ;
    END
  END bidir_pd[0]
  PIN bidir_pd[10]
    DIRECTION OUTPUT ;
    USE SIGNAL ;
    ANTENNADIFFAREA 0.360800 ;
    PORT
      LAYER Metal2 ;
        RECT 565.600 0.000 566.160 0.560 ;
    END
  END bidir_pd[10]
  PIN bidir_pd[11]
    DIRECTION OUTPUT ;
    USE SIGNAL ;
    ANTENNADIFFAREA 0.360800 ;
    PORT
      LAYER Metal3 ;
        RECT 1099.440 566.720 1100.000 567.280 ;
    END
  END bidir_pd[11]
  PIN bidir_pd[12]
    DIRECTION OUTPUT ;
    USE SIGNAL ;
    ANTENNADIFFAREA 0.360800 ;
    PORT
      LAYER Metal3 ;
        RECT 1099.440 576.800 1100.000 577.360 ;
    END
  END bidir_pd[12]
  PIN bidir_pd[13]
    DIRECTION OUTPUT ;
    USE SIGNAL ;
    ANTENNADIFFAREA 0.360800 ;
    PORT
      LAYER Metal3 ;
        RECT 1099.440 591.360 1100.000 591.920 ;
    END
  END bidir_pd[13]
  PIN bidir_pd[14]
    DIRECTION OUTPUT ;
    USE SIGNAL ;
    ANTENNADIFFAREA 0.360800 ;
    PORT
      LAYER Metal2 ;
        RECT 599.200 0.000 599.760 0.560 ;
    END
  END bidir_pd[14]
  PIN bidir_pd[15]
    DIRECTION OUTPUT ;
    USE SIGNAL ;
    ANTENNADIFFAREA 0.360800 ;
    PORT
      LAYER Metal3 ;
        RECT 1099.440 604.800 1100.000 605.360 ;
    END
  END bidir_pd[15]
  PIN bidir_pd[16]
    DIRECTION OUTPUT ;
    USE SIGNAL ;
    ANTENNADIFFAREA 0.360800 ;
    PORT
      LAYER Metal2 ;
        RECT 504.000 0.000 504.560 0.560 ;
    END
  END bidir_pd[16]
  PIN bidir_pd[17]
    DIRECTION OUTPUT ;
    USE SIGNAL ;
    ANTENNADIFFAREA 0.360800 ;
    PORT
      LAYER Metal2 ;
        RECT 549.920 0.000 550.480 0.560 ;
    END
  END bidir_pd[17]
  PIN bidir_pd[18]
    DIRECTION OUTPUT ;
    USE SIGNAL ;
    ANTENNADIFFAREA 0.360800 ;
    PORT
      LAYER Metal3 ;
        RECT 1099.440 549.920 1100.000 550.480 ;
    END
  END bidir_pd[18]
  PIN bidir_pd[19]
    DIRECTION OUTPUT ;
    USE SIGNAL ;
    ANTENNADIFFAREA 0.360800 ;
    PORT
      LAYER Metal3 ;
        RECT 1099.440 602.560 1100.000 603.120 ;
    END
  END bidir_pd[19]
  PIN bidir_pd[1]
    DIRECTION OUTPUT ;
    USE SIGNAL ;
    ANTENNADIFFAREA 0.360800 ;
    PORT
      LAYER Metal2 ;
        RECT 583.520 1099.440 584.080 1100.000 ;
    END
  END bidir_pd[1]
  PIN bidir_pd[20]
    DIRECTION OUTPUT ;
    USE SIGNAL ;
    ANTENNADIFFAREA 0.360800 ;
    PORT
      LAYER Metal2 ;
        RECT 528.640 0.000 529.200 0.560 ;
    END
  END bidir_pd[20]
  PIN bidir_pd[21]
    DIRECTION OUTPUT ;
    USE SIGNAL ;
    ANTENNADIFFAREA 0.360800 ;
    PORT
      LAYER Metal2 ;
        RECT 543.200 0.000 543.760 0.560 ;
    END
  END bidir_pd[21]
  PIN bidir_pd[22]
    DIRECTION OUTPUT ;
    USE SIGNAL ;
    ANTENNADIFFAREA 0.360800 ;
    PORT
      LAYER Metal2 ;
        RECT 602.560 0.000 603.120 0.560 ;
    END
  END bidir_pd[22]
  PIN bidir_pd[23]
    DIRECTION OUTPUT ;
    USE SIGNAL ;
    ANTENNADIFFAREA 0.360800 ;
    PORT
      LAYER Metal3 ;
        RECT 1099.440 516.320 1100.000 516.880 ;
    END
  END bidir_pd[23]
  PIN bidir_pd[24]
    DIRECTION OUTPUT ;
    USE SIGNAL ;
    ANTENNADIFFAREA 0.360800 ;
    PORT
      LAYER Metal2 ;
        RECT 581.280 1099.440 581.840 1100.000 ;
    END
  END bidir_pd[24]
  PIN bidir_pd[25]
    DIRECTION OUTPUT ;
    USE SIGNAL ;
    ANTENNADIFFAREA 0.360800 ;
    PORT
      LAYER Metal2 ;
        RECT 590.240 0.000 590.800 0.560 ;
    END
  END bidir_pd[25]
  PIN bidir_pd[26]
    DIRECTION OUTPUT ;
    USE SIGNAL ;
    ANTENNADIFFAREA 0.360800 ;
    PORT
      LAYER Metal2 ;
        RECT 520.800 1099.440 521.360 1100.000 ;
    END
  END bidir_pd[26]
  PIN bidir_pd[27]
    DIRECTION OUTPUT ;
    USE SIGNAL ;
    ANTENNADIFFAREA 0.360800 ;
    PORT
      LAYER Metal2 ;
        RECT 510.720 0.000 511.280 0.560 ;
    END
  END bidir_pd[27]
  PIN bidir_pd[28]
    DIRECTION OUTPUT ;
    USE SIGNAL ;
    ANTENNADIFFAREA 0.360800 ;
    PORT
      LAYER Metal2 ;
        RECT 572.320 0.000 572.880 0.560 ;
    END
  END bidir_pd[28]
  PIN bidir_pd[29]
    DIRECTION OUTPUT ;
    USE SIGNAL ;
    ANTENNADIFFAREA 0.360800 ;
    PORT
      LAYER Metal2 ;
        RECT 501.760 0.000 502.320 0.560 ;
    END
  END bidir_pd[29]
  PIN bidir_pd[2]
    DIRECTION OUTPUT ;
    USE SIGNAL ;
    ANTENNADIFFAREA 0.360800 ;
    PORT
      LAYER Metal2 ;
        RECT 558.880 1099.440 559.440 1100.000 ;
    END
  END bidir_pd[2]
  PIN bidir_pd[30]
    DIRECTION OUTPUT ;
    USE SIGNAL ;
    ANTENNADIFFAREA 0.360800 ;
    PORT
      LAYER Metal2 ;
        RECT 548.800 0.000 549.360 0.560 ;
    END
  END bidir_pd[30]
  PIN bidir_pd[31]
    DIRECTION OUTPUT ;
    USE SIGNAL ;
    ANTENNADIFFAREA 0.360800 ;
    PORT
      LAYER Metal2 ;
        RECT 527.520 1099.440 528.080 1100.000 ;
    END
  END bidir_pd[31]
  PIN bidir_pd[32]
    DIRECTION OUTPUT ;
    USE SIGNAL ;
    ANTENNADIFFAREA 0.360800 ;
    PORT
      LAYER Metal3 ;
        RECT 1099.440 514.080 1100.000 514.640 ;
    END
  END bidir_pd[32]
  PIN bidir_pd[33]
    DIRECTION OUTPUT ;
    USE SIGNAL ;
    ANTENNADIFFAREA 0.360800 ;
    PORT
      LAYER Metal2 ;
        RECT 537.600 0.000 538.160 0.560 ;
    END
  END bidir_pd[33]
  PIN bidir_pd[34]
    DIRECTION OUTPUT ;
    USE SIGNAL ;
    ANTENNADIFFAREA 0.360800 ;
    PORT
      LAYER Metal3 ;
        RECT 1099.440 585.760 1100.000 586.320 ;
    END
  END bidir_pd[34]
  PIN bidir_pd[35]
    DIRECTION OUTPUT ;
    USE SIGNAL ;
    ANTENNADIFFAREA 0.360800 ;
    PORT
      LAYER Metal3 ;
        RECT 1099.440 598.080 1100.000 598.640 ;
    END
  END bidir_pd[35]
  PIN bidir_pd[36]
    DIRECTION OUTPUT ;
    USE SIGNAL ;
    ANTENNADIFFAREA 0.360800 ;
    PORT
      LAYER Metal2 ;
        RECT 516.320 0.000 516.880 0.560 ;
    END
  END bidir_pd[36]
  PIN bidir_pd[37]
    DIRECTION OUTPUT ;
    USE SIGNAL ;
    ANTENNADIFFAREA 0.360800 ;
    PORT
      LAYER Metal2 ;
        RECT 516.320 1099.440 516.880 1100.000 ;
    END
  END bidir_pd[37]
  PIN bidir_pd[38]
    DIRECTION OUTPUT ;
    USE SIGNAL ;
    ANTENNADIFFAREA 0.360800 ;
    PORT
      LAYER Metal2 ;
        RECT 622.720 0.000 623.280 0.560 ;
    END
  END bidir_pd[38]
  PIN bidir_pd[39]
    DIRECTION OUTPUT ;
    USE SIGNAL ;
    ANTENNADIFFAREA 0.360800 ;
    PORT
      LAYER Metal3 ;
        RECT 1099.440 544.320 1100.000 544.880 ;
    END
  END bidir_pd[39]
  PIN bidir_pd[3]
    DIRECTION OUTPUT ;
    USE SIGNAL ;
    ANTENNADIFFAREA 0.360800 ;
    PORT
      LAYER Metal2 ;
        RECT 573.440 1099.440 574.000 1100.000 ;
    END
  END bidir_pd[3]
  PIN bidir_pd[4]
    DIRECTION OUTPUT ;
    USE SIGNAL ;
    ANTENNADIFFAREA 0.360800 ;
    PORT
      LAYER Metal2 ;
        RECT 575.680 1099.440 576.240 1100.000 ;
    END
  END bidir_pd[4]
  PIN bidir_pd[5]
    DIRECTION OUTPUT ;
    USE SIGNAL ;
    ANTENNADIFFAREA 0.360800 ;
    PORT
      LAYER Metal2 ;
        RECT 532.000 1099.440 532.560 1100.000 ;
    END
  END bidir_pd[5]
  PIN bidir_pd[6]
    DIRECTION OUTPUT ;
    USE SIGNAL ;
    ANTENNADIFFAREA 0.360800 ;
    PORT
      LAYER Metal2 ;
        RECT 521.920 1099.440 522.480 1100.000 ;
    END
  END bidir_pd[6]
  PIN bidir_pd[7]
    DIRECTION OUTPUT ;
    USE SIGNAL ;
    ANTENNADIFFAREA 0.360800 ;
    PORT
      LAYER Metal3 ;
        RECT 1099.440 558.880 1100.000 559.440 ;
    END
  END bidir_pd[7]
  PIN bidir_pd[8]
    DIRECTION OUTPUT ;
    USE SIGNAL ;
    ANTENNADIFFAREA 0.360800 ;
    PORT
      LAYER Metal2 ;
        RECT 502.880 0.000 503.440 0.560 ;
    END
  END bidir_pd[8]
  PIN bidir_pd[9]
    DIRECTION OUTPUT ;
    USE SIGNAL ;
    ANTENNADIFFAREA 0.360800 ;
    PORT
      LAYER Metal2 ;
        RECT 573.440 0.000 574.000 0.560 ;
    END
  END bidir_pd[9]
  PIN bidir_pu[0]
    DIRECTION OUTPUT ;
    USE SIGNAL ;
    ANTENNADIFFAREA 0.360800 ;
    PORT
      LAYER Metal2 ;
        RECT 574.560 1099.440 575.120 1100.000 ;
    END
  END bidir_pu[0]
  PIN bidir_pu[10]
    DIRECTION OUTPUT ;
    USE SIGNAL ;
    ANTENNADIFFAREA 0.360800 ;
    PORT
      LAYER Metal2 ;
        RECT 519.680 0.000 520.240 0.560 ;
    END
  END bidir_pu[10]
  PIN bidir_pu[11]
    DIRECTION OUTPUT ;
    USE SIGNAL ;
    ANTENNADIFFAREA 0.360800 ;
    PORT
      LAYER Metal2 ;
        RECT 612.640 0.000 613.200 0.560 ;
    END
  END bidir_pu[11]
  PIN bidir_pu[12]
    DIRECTION OUTPUT ;
    USE SIGNAL ;
    ANTENNADIFFAREA 0.360800 ;
    PORT
      LAYER Metal3 ;
        RECT 1099.440 556.640 1100.000 557.200 ;
    END
  END bidir_pu[12]
  PIN bidir_pu[13]
    DIRECTION OUTPUT ;
    USE SIGNAL ;
    ANTENNADIFFAREA 0.360800 ;
    PORT
      LAYER Metal3 ;
        RECT 1099.440 575.680 1100.000 576.240 ;
    END
  END bidir_pu[13]
  PIN bidir_pu[14]
    DIRECTION OUTPUT ;
    USE SIGNAL ;
    ANTENNADIFFAREA 0.360800 ;
    PORT
      LAYER Metal2 ;
        RECT 567.840 1099.440 568.400 1100.000 ;
    END
  END bidir_pu[14]
  PIN bidir_pu[15]
    DIRECTION OUTPUT ;
    USE SIGNAL ;
    ANTENNADIFFAREA 0.360800 ;
    PORT
      LAYER Metal2 ;
        RECT 626.080 0.000 626.640 0.560 ;
    END
  END bidir_pu[15]
  PIN bidir_pu[16]
    DIRECTION OUTPUT ;
    USE SIGNAL ;
    ANTENNADIFFAREA 0.360800 ;
    PORT
      LAYER Metal2 ;
        RECT 593.600 0.000 594.160 0.560 ;
    END
  END bidir_pu[16]
  PIN bidir_pu[17]
    DIRECTION OUTPUT ;
    USE SIGNAL ;
    ANTENNADIFFAREA 0.360800 ;
    PORT
      LAYER Metal2 ;
        RECT 589.120 0.000 589.680 0.560 ;
    END
  END bidir_pu[17]
  PIN bidir_pu[18]
    DIRECTION OUTPUT ;
    USE SIGNAL ;
    ANTENNADIFFAREA 0.360800 ;
    PORT
      LAYER Metal2 ;
        RECT 529.760 0.000 530.320 0.560 ;
    END
  END bidir_pu[18]
  PIN bidir_pu[19]
    DIRECTION OUTPUT ;
    USE SIGNAL ;
    ANTENNADIFFAREA 0.360800 ;
    PORT
      LAYER Metal3 ;
        RECT 1099.440 542.080 1100.000 542.640 ;
    END
  END bidir_pu[19]
  PIN bidir_pu[1]
    DIRECTION OUTPUT ;
    USE SIGNAL ;
    ANTENNADIFFAREA 0.360800 ;
    PORT
      LAYER Metal3 ;
        RECT 1099.440 535.360 1100.000 535.920 ;
    END
  END bidir_pu[1]
  PIN bidir_pu[20]
    DIRECTION OUTPUT ;
    USE SIGNAL ;
    ANTENNADIFFAREA 0.360800 ;
    PORT
      LAYER Metal2 ;
        RECT 546.560 1099.440 547.120 1100.000 ;
    END
  END bidir_pu[20]
  PIN bidir_pu[21]
    DIRECTION OUTPUT ;
    USE SIGNAL ;
    ANTENNADIFFAREA 0.360800 ;
    PORT
      LAYER Metal2 ;
        RECT 525.280 1099.440 525.840 1100.000 ;
    END
  END bidir_pu[21]
  PIN bidir_pu[22]
    DIRECTION OUTPUT ;
    USE SIGNAL ;
    ANTENNADIFFAREA 0.360800 ;
    PORT
      LAYER Metal3 ;
        RECT 1099.440 588.000 1100.000 588.560 ;
    END
  END bidir_pu[22]
  PIN bidir_pu[23]
    DIRECTION OUTPUT ;
    USE SIGNAL ;
    ANTENNADIFFAREA 0.360800 ;
    PORT
      LAYER Metal3 ;
        RECT 1099.440 582.400 1100.000 582.960 ;
    END
  END bidir_pu[23]
  PIN bidir_pu[24]
    DIRECTION OUTPUT ;
    USE SIGNAL ;
    ANTENNADIFFAREA 0.360800 ;
    PORT
      LAYER Metal2 ;
        RECT 568.960 0.000 569.520 0.560 ;
    END
  END bidir_pu[24]
  PIN bidir_pu[25]
    DIRECTION OUTPUT ;
    USE SIGNAL ;
    ANTENNADIFFAREA 0.360800 ;
    PORT
      LAYER Metal3 ;
        RECT 1099.440 525.280 1100.000 525.840 ;
    END
  END bidir_pu[25]
  PIN bidir_pu[26]
    DIRECTION OUTPUT ;
    USE SIGNAL ;
    ANTENNADIFFAREA 0.360800 ;
    PORT
      LAYER Metal3 ;
        RECT 1099.440 548.800 1100.000 549.360 ;
    END
  END bidir_pu[26]
  PIN bidir_pu[27]
    DIRECTION OUTPUT ;
    USE SIGNAL ;
    ANTENNADIFFAREA 0.360800 ;
    PORT
      LAYER Metal2 ;
        RECT 580.160 0.000 580.720 0.560 ;
    END
  END bidir_pu[27]
  PIN bidir_pu[28]
    DIRECTION OUTPUT ;
    USE SIGNAL ;
    ANTENNADIFFAREA 0.360800 ;
    PORT
      LAYER Metal3 ;
        RECT 1099.440 528.640 1100.000 529.200 ;
    END
  END bidir_pu[28]
  PIN bidir_pu[29]
    DIRECTION OUTPUT ;
    USE SIGNAL ;
    ANTENNADIFFAREA 0.360800 ;
    PORT
      LAYER Metal2 ;
        RECT 617.120 0.000 617.680 0.560 ;
    END
  END bidir_pu[29]
  PIN bidir_pu[2]
    DIRECTION OUTPUT ;
    USE SIGNAL ;
    ANTENNADIFFAREA 0.360800 ;
    PORT
      LAYER Metal2 ;
        RECT 506.240 1099.440 506.800 1100.000 ;
    END
  END bidir_pu[2]
  PIN bidir_pu[30]
    DIRECTION OUTPUT ;
    USE SIGNAL ;
    ANTENNADIFFAREA 0.360800 ;
    PORT
      LAYER Metal3 ;
        RECT 1099.440 567.840 1100.000 568.400 ;
    END
  END bidir_pu[30]
  PIN bidir_pu[31]
    DIRECTION OUTPUT ;
    USE SIGNAL ;
    ANTENNADIFFAREA 0.360800 ;
    PORT
      LAYER Metal2 ;
        RECT 525.280 0.000 525.840 0.560 ;
    END
  END bidir_pu[31]
  PIN bidir_pu[32]
    DIRECTION OUTPUT ;
    USE SIGNAL ;
    ANTENNADIFFAREA 0.360800 ;
    PORT
      LAYER Metal2 ;
        RECT 598.080 0.000 598.640 0.560 ;
    END
  END bidir_pu[32]
  PIN bidir_pu[33]
    DIRECTION OUTPUT ;
    USE SIGNAL ;
    ANTENNADIFFAREA 0.360800 ;
    PORT
      LAYER Metal2 ;
        RECT 588.000 1099.440 588.560 1100.000 ;
    END
  END bidir_pu[33]
  PIN bidir_pu[34]
    DIRECTION OUTPUT ;
    USE SIGNAL ;
    ANTENNADIFFAREA 0.360800 ;
    PORT
      LAYER Metal3 ;
        RECT 1099.440 586.880 1100.000 587.440 ;
    END
  END bidir_pu[34]
  PIN bidir_pu[35]
    DIRECTION OUTPUT ;
    USE SIGNAL ;
    ANTENNADIFFAREA 0.360800 ;
    PORT
      LAYER Metal2 ;
        RECT 560.000 0.000 560.560 0.560 ;
    END
  END bidir_pu[35]
  PIN bidir_pu[36]
    DIRECTION OUTPUT ;
    USE SIGNAL ;
    ANTENNADIFFAREA 0.360800 ;
    PORT
      LAYER Metal3 ;
        RECT 1099.440 538.720 1100.000 539.280 ;
    END
  END bidir_pu[36]
  PIN bidir_pu[37]
    DIRECTION OUTPUT ;
    USE SIGNAL ;
    ANTENNADIFFAREA 0.360800 ;
    PORT
      LAYER Metal3 ;
        RECT 1099.440 593.600 1100.000 594.160 ;
    END
  END bidir_pu[37]
  PIN bidir_pu[38]
    DIRECTION OUTPUT ;
    USE SIGNAL ;
    ANTENNADIFFAREA 0.360800 ;
    PORT
      LAYER Metal2 ;
        RECT 571.200 1099.440 571.760 1100.000 ;
    END
  END bidir_pu[38]
  PIN bidir_pu[39]
    DIRECTION OUTPUT ;
    USE SIGNAL ;
    ANTENNADIFFAREA 0.360800 ;
    PORT
      LAYER Metal2 ;
        RECT 534.240 0.000 534.800 0.560 ;
    END
  END bidir_pu[39]
  PIN bidir_pu[3]
    DIRECTION OUTPUT ;
    USE SIGNAL ;
    ANTENNADIFFAREA 0.360800 ;
    PORT
      LAYER Metal3 ;
        RECT 1099.440 589.120 1100.000 589.680 ;
    END
  END bidir_pu[3]
  PIN bidir_pu[4]
    DIRECTION OUTPUT ;
    USE SIGNAL ;
    ANTENNADIFFAREA 0.360800 ;
    PORT
      LAYER Metal3 ;
        RECT 1099.440 584.640 1100.000 585.200 ;
    END
  END bidir_pu[4]
  PIN bidir_pu[5]
    DIRECTION OUTPUT ;
    USE SIGNAL ;
    ANTENNADIFFAREA 0.360800 ;
    PORT
      LAYER Metal3 ;
        RECT 1099.440 530.880 1100.000 531.440 ;
    END
  END bidir_pu[5]
  PIN bidir_pu[6]
    DIRECTION OUTPUT ;
    USE SIGNAL ;
    ANTENNADIFFAREA 0.360800 ;
    PORT
      LAYER Metal2 ;
        RECT 538.720 0.000 539.280 0.560 ;
    END
  END bidir_pu[6]
  PIN bidir_pu[7]
    DIRECTION OUTPUT ;
    USE SIGNAL ;
    ANTENNADIFFAREA 0.360800 ;
    PORT
      LAYER Metal2 ;
        RECT 534.240 1099.440 534.800 1100.000 ;
    END
  END bidir_pu[7]
  PIN bidir_pu[8]
    DIRECTION OUTPUT ;
    USE SIGNAL ;
    ANTENNADIFFAREA 0.360800 ;
    PORT
      LAYER Metal2 ;
        RECT 557.760 1099.440 558.320 1100.000 ;
    END
  END bidir_pu[8]
  PIN bidir_pu[9]
    DIRECTION OUTPUT ;
    USE SIGNAL ;
    ANTENNADIFFAREA 0.360800 ;
    PORT
      LAYER Metal2 ;
        RECT 583.520 0.000 584.080 0.560 ;
    END
  END bidir_pu[9]
  PIN bidir_sl[0]
    DIRECTION OUTPUT ;
    USE SIGNAL ;
    ANTENNADIFFAREA 0.360800 ;
    PORT
      LAYER Metal3 ;
        RECT 1099.440 580.160 1100.000 580.720 ;
    END
  END bidir_sl[0]
  PIN bidir_sl[10]
    DIRECTION OUTPUT ;
    USE SIGNAL ;
    ANTENNADIFFAREA 0.360800 ;
    PORT
      LAYER Metal3 ;
        RECT 1099.440 583.520 1100.000 584.080 ;
    END
  END bidir_sl[10]
  PIN bidir_sl[11]
    DIRECTION OUTPUT ;
    USE SIGNAL ;
    ANTENNADIFFAREA 0.360800 ;
    PORT
      LAYER Metal2 ;
        RECT 545.440 1099.440 546.000 1100.000 ;
    END
  END bidir_sl[11]
  PIN bidir_sl[12]
    DIRECTION OUTPUT ;
    USE SIGNAL ;
    ANTENNADIFFAREA 0.360800 ;
    PORT
      LAYER Metal2 ;
        RECT 603.680 0.000 604.240 0.560 ;
    END
  END bidir_sl[12]
  PIN bidir_sl[13]
    DIRECTION OUTPUT ;
    USE SIGNAL ;
    ANTENNADIFFAREA 0.360800 ;
    PORT
      LAYER Metal3 ;
        RECT 1099.440 515.200 1100.000 515.760 ;
    END
  END bidir_sl[13]
  PIN bidir_sl[14]
    DIRECTION OUTPUT ;
    USE SIGNAL ;
    ANTENNADIFFAREA 0.360800 ;
    PORT
      LAYER Metal2 ;
        RECT 579.040 1099.440 579.600 1100.000 ;
    END
  END bidir_sl[14]
  PIN bidir_sl[15]
    DIRECTION OUTPUT ;
    USE SIGNAL ;
    ANTENNADIFFAREA 0.360800 ;
    PORT
      LAYER Metal3 ;
        RECT 1099.440 568.960 1100.000 569.520 ;
    END
  END bidir_sl[15]
  PIN bidir_sl[16]
    DIRECTION OUTPUT ;
    USE SIGNAL ;
    ANTENNADIFFAREA 0.360800 ;
    PORT
      LAYER Metal2 ;
        RECT 553.280 1099.440 553.840 1100.000 ;
    END
  END bidir_sl[16]
  PIN bidir_sl[17]
    DIRECTION OUTPUT ;
    USE SIGNAL ;
    ANTENNADIFFAREA 0.360800 ;
    PORT
      LAYER Metal2 ;
        RECT 586.880 0.000 587.440 0.560 ;
    END
  END bidir_sl[17]
  PIN bidir_sl[18]
    DIRECTION OUTPUT ;
    USE SIGNAL ;
    ANTENNADIFFAREA 0.360800 ;
    PORT
      LAYER Metal2 ;
        RECT 557.760 0.000 558.320 0.560 ;
    END
  END bidir_sl[18]
  PIN bidir_sl[19]
    DIRECTION OUTPUT ;
    USE SIGNAL ;
    ANTENNADIFFAREA 0.360800 ;
    PORT
      LAYER Metal3 ;
        RECT 1099.440 603.680 1100.000 604.240 ;
    END
  END bidir_sl[19]
  PIN bidir_sl[1]
    DIRECTION OUTPUT ;
    USE SIGNAL ;
    ANTENNADIFFAREA 0.360800 ;
    PORT
      LAYER Metal3 ;
        RECT 1099.440 574.560 1100.000 575.120 ;
    END
  END bidir_sl[1]
  PIN bidir_sl[20]
    DIRECTION OUTPUT ;
    USE SIGNAL ;
    ANTENNADIFFAREA 0.360800 ;
    PORT
      LAYER Metal2 ;
        RECT 610.400 0.000 610.960 0.560 ;
    END
  END bidir_sl[20]
  PIN bidir_sl[21]
    DIRECTION OUTPUT ;
    USE SIGNAL ;
    ANTENNADIFFAREA 0.360800 ;
    PORT
      LAYER Metal3 ;
        RECT 1099.440 518.560 1100.000 519.120 ;
    END
  END bidir_sl[21]
  PIN bidir_sl[22]
    DIRECTION OUTPUT ;
    USE SIGNAL ;
    ANTENNADIFFAREA 0.360800 ;
    PORT
      LAYER Metal2 ;
        RECT 591.360 1099.440 591.920 1100.000 ;
    END
  END bidir_sl[22]
  PIN bidir_sl[23]
    DIRECTION OUTPUT ;
    USE SIGNAL ;
    ANTENNADIFFAREA 0.360800 ;
    PORT
      LAYER Metal3 ;
        RECT 1099.440 599.200 1100.000 599.760 ;
    END
  END bidir_sl[23]
  PIN bidir_sl[24]
    DIRECTION OUTPUT ;
    USE SIGNAL ;
    ANTENNADIFFAREA 0.360800 ;
    PORT
      LAYER Metal2 ;
        RECT 528.640 1099.440 529.200 1100.000 ;
    END
  END bidir_sl[24]
  PIN bidir_sl[25]
    DIRECTION OUTPUT ;
    USE SIGNAL ;
    ANTENNADIFFAREA 0.360800 ;
    PORT
      LAYER Metal3 ;
        RECT 1099.440 577.920 1100.000 578.480 ;
    END
  END bidir_sl[25]
  PIN bidir_sl[26]
    DIRECTION OUTPUT ;
    USE SIGNAL ;
    ANTENNADIFFAREA 0.360800 ;
    PORT
      LAYER Metal3 ;
        RECT 1099.440 563.360 1100.000 563.920 ;
    END
  END bidir_sl[26]
  PIN bidir_sl[27]
    DIRECTION OUTPUT ;
    USE SIGNAL ;
    ANTENNADIFFAREA 0.360800 ;
    PORT
      LAYER Metal2 ;
        RECT 611.520 0.000 612.080 0.560 ;
    END
  END bidir_sl[27]
  PIN bidir_sl[28]
    DIRECTION OUTPUT ;
    USE SIGNAL ;
    ANTENNADIFFAREA 0.360800 ;
    PORT
      LAYER Metal2 ;
        RECT 609.280 0.000 609.840 0.560 ;
    END
  END bidir_sl[28]
  PIN bidir_sl[29]
    DIRECTION OUTPUT ;
    USE SIGNAL ;
    ANTENNADIFFAREA 0.360800 ;
    PORT
      LAYER Metal2 ;
        RECT 509.600 1099.440 510.160 1100.000 ;
    END
  END bidir_sl[29]
  PIN bidir_sl[2]
    DIRECTION OUTPUT ;
    USE SIGNAL ;
    ANTENNADIFFAREA 0.360800 ;
    PORT
      LAYER Metal2 ;
        RECT 582.400 1099.440 582.960 1100.000 ;
    END
  END bidir_sl[2]
  PIN bidir_sl[30]
    DIRECTION OUTPUT ;
    USE SIGNAL ;
    ANTENNADIFFAREA 0.360800 ;
    PORT
      LAYER Metal2 ;
        RECT 560.000 1099.440 560.560 1100.000 ;
    END
  END bidir_sl[30]
  PIN bidir_sl[31]
    DIRECTION OUTPUT ;
    USE SIGNAL ;
    ANTENNADIFFAREA 0.360800 ;
    PORT
      LAYER Metal2 ;
        RECT 544.320 0.000 544.880 0.560 ;
    END
  END bidir_sl[31]
  PIN bidir_sl[32]
    DIRECTION OUTPUT ;
    USE SIGNAL ;
    ANTENNADIFFAREA 0.360800 ;
    PORT
      LAYER Metal3 ;
        RECT 1099.440 561.120 1100.000 561.680 ;
    END
  END bidir_sl[32]
  PIN bidir_sl[33]
    DIRECTION OUTPUT ;
    USE SIGNAL ;
    ANTENNADIFFAREA 0.360800 ;
    PORT
      LAYER Metal2 ;
        RECT 623.840 0.000 624.400 0.560 ;
    END
  END bidir_sl[33]
  PIN bidir_sl[34]
    DIRECTION OUTPUT ;
    USE SIGNAL ;
    ANTENNADIFFAREA 0.360800 ;
    PORT
      LAYER Metal2 ;
        RECT 536.480 1099.440 537.040 1100.000 ;
    END
  END bidir_sl[34]
  PIN bidir_sl[35]
    DIRECTION OUTPUT ;
    USE SIGNAL ;
    ANTENNADIFFAREA 0.360800 ;
    PORT
      LAYER Metal2 ;
        RECT 555.520 0.000 556.080 0.560 ;
    END
  END bidir_sl[35]
  PIN bidir_sl[36]
    DIRECTION OUTPUT ;
    USE SIGNAL ;
    ANTENNADIFFAREA 0.360800 ;
    PORT
      LAYER Metal2 ;
        RECT 595.840 0.000 596.400 0.560 ;
    END
  END bidir_sl[36]
  PIN bidir_sl[37]
    DIRECTION OUTPUT ;
    USE SIGNAL ;
    ANTENNADIFFAREA 0.360800 ;
    PORT
      LAYER Metal2 ;
        RECT 515.200 1099.440 515.760 1100.000 ;
    END
  END bidir_sl[37]
  PIN bidir_sl[38]
    DIRECTION OUTPUT ;
    USE SIGNAL ;
    ANTENNADIFFAREA 0.360800 ;
    PORT
      LAYER Metal2 ;
        RECT 577.920 0.000 578.480 0.560 ;
    END
  END bidir_sl[38]
  PIN bidir_sl[39]
    DIRECTION OUTPUT ;
    USE SIGNAL ;
    ANTENNADIFFAREA 0.360800 ;
    PORT
      LAYER Metal2 ;
        RECT 574.560 0.000 575.120 0.560 ;
    END
  END bidir_sl[39]
  PIN bidir_sl[3]
    DIRECTION OUTPUT ;
    USE SIGNAL ;
    ANTENNADIFFAREA 0.360800 ;
    PORT
      LAYER Metal2 ;
        RECT 568.960 1099.440 569.520 1100.000 ;
    END
  END bidir_sl[3]
  PIN bidir_sl[4]
    DIRECTION OUTPUT ;
    USE SIGNAL ;
    ANTENNADIFFAREA 0.360800 ;
    PORT
      LAYER Metal2 ;
        RECT 526.400 1099.440 526.960 1100.000 ;
    END
  END bidir_sl[4]
  PIN bidir_sl[5]
    DIRECTION OUTPUT ;
    USE SIGNAL ;
    ANTENNADIFFAREA 0.360800 ;
    PORT
      LAYER Metal2 ;
        RECT 592.480 0.000 593.040 0.560 ;
    END
  END bidir_sl[5]
  PIN bidir_sl[6]
    DIRECTION OUTPUT ;
    USE SIGNAL ;
    ANTENNADIFFAREA 0.360800 ;
    PORT
      LAYER Metal2 ;
        RECT 566.720 0.000 567.280 0.560 ;
    END
  END bidir_sl[6]
  PIN bidir_sl[7]
    DIRECTION OUTPUT ;
    USE SIGNAL ;
    ANTENNADIFFAREA 0.360800 ;
    PORT
      LAYER Metal2 ;
        RECT 579.040 0.000 579.600 0.560 ;
    END
  END bidir_sl[7]
  PIN bidir_sl[8]
    DIRECTION OUTPUT ;
    USE SIGNAL ;
    ANTENNADIFFAREA 0.360800 ;
    PORT
      LAYER Metal2 ;
        RECT 500.640 1099.440 501.200 1100.000 ;
    END
  END bidir_sl[8]
  PIN bidir_sl[9]
    DIRECTION OUTPUT ;
    USE SIGNAL ;
    ANTENNADIFFAREA 0.360800 ;
    PORT
      LAYER Metal2 ;
        RECT 514.080 1099.440 514.640 1100.000 ;
    END
  END bidir_sl[9]
  PIN clk
    DIRECTION INPUT ;
    USE SIGNAL ;
    ANTENNAGATEAREA 4.738000 ;
    ANTENNADIFFAREA 0.410400 ;
    PORT
      LAYER Metal3 ;
        RECT 0.000 576.800 0.560 577.360 ;
    END
  END clk
  PIN input_in
    DIRECTION INPUT ;
    USE SIGNAL ;
    ANTENNAGATEAREA 1.102000 ;
    ANTENNADIFFAREA 0.410400 ;
    PORT
      LAYER Metal2 ;
        RECT 542.080 0.000 542.640 0.560 ;
    END
  END input_in
  PIN input_pd
    DIRECTION OUTPUT ;
    USE SIGNAL ;
    ANTENNADIFFAREA 0.360800 ;
    PORT
      LAYER Metal2 ;
        RECT 529.760 1099.440 530.320 1100.000 ;
    END
  END input_pd
  PIN input_pu
    DIRECTION OUTPUT ;
    USE SIGNAL ;
    ANTENNADIFFAREA 0.360800 ;
    PORT
      LAYER Metal2 ;
        RECT 607.040 0.000 607.600 0.560 ;
    END
  END input_pu
  PIN rst_n
    DIRECTION INPUT ;
    USE SIGNAL ;
    ANTENNAGATEAREA 0.396000 ;
    ANTENNADIFFAREA 0.410400 ;
    PORT
      LAYER Metal3 ;
        RECT 0.000 571.200 0.560 571.760 ;
    END
  END rst_n
  OBS
      LAYER Nwell ;
        RECT 6.290 15.250 1093.550 1082.350 ;
      LAYER Metal1 ;
        RECT 6.720 15.380 1093.120 1082.220 ;
      LAYER Metal2 ;
        RECT 8.540 1077.830 20.240 1099.860 ;
        RECT 25.840 1081.750 110.240 1099.860 ;
        RECT 115.840 1081.750 200.240 1099.860 ;
        RECT 25.840 1077.830 200.240 1081.750 ;
        RECT 205.840 1081.750 290.240 1099.860 ;
        RECT 295.840 1081.750 380.240 1099.860 ;
        RECT 205.840 1077.830 380.240 1081.750 ;
        RECT 385.840 1081.750 470.240 1099.860 ;
        RECT 475.840 1099.140 492.500 1099.860 ;
        RECT 494.780 1099.140 498.100 1099.860 ;
        RECT 501.500 1099.140 504.820 1099.860 ;
        RECT 595.580 1099.140 650.240 1099.860 ;
        RECT 475.840 1081.750 560.240 1099.140 ;
        RECT 385.840 1077.830 560.240 1081.750 ;
        RECT 565.840 1081.750 650.240 1099.140 ;
        RECT 655.840 1081.750 740.240 1099.860 ;
        RECT 565.840 1077.830 740.240 1081.750 ;
        RECT 745.840 1081.750 830.240 1099.860 ;
        RECT 835.840 1081.750 920.240 1099.860 ;
        RECT 745.840 1077.830 920.240 1081.750 ;
        RECT 925.840 1081.750 1010.240 1099.860 ;
        RECT 1015.840 1081.750 1093.540 1099.860 ;
        RECT 925.840 1077.830 1093.540 1081.750 ;
        RECT 8.540 19.770 1093.540 1077.830 ;
        RECT 8.540 0.860 20.240 19.770 ;
        RECT 25.840 15.850 200.240 19.770 ;
        RECT 25.840 0.860 110.240 15.850 ;
        RECT 32.220 0.560 110.240 0.860 ;
        RECT 115.840 0.560 200.240 15.850 ;
        RECT 205.840 15.850 380.240 19.770 ;
        RECT 205.840 0.560 290.240 15.850 ;
        RECT 295.840 0.560 380.240 15.850 ;
        RECT 385.840 15.850 560.240 19.770 ;
        RECT 385.840 0.560 470.240 15.850 ;
        RECT 475.840 0.860 560.240 15.850 ;
        RECT 565.840 15.850 740.240 19.770 ;
        RECT 565.840 0.860 650.240 15.850 ;
        RECT 475.840 0.560 500.340 0.860 ;
        RECT 628.060 0.560 650.240 0.860 ;
        RECT 655.840 0.560 740.240 15.850 ;
        RECT 745.840 15.850 920.240 19.770 ;
        RECT 745.840 0.560 830.240 15.850 ;
        RECT 835.840 0.560 920.240 15.850 ;
        RECT 925.840 15.850 1093.540 19.770 ;
        RECT 925.840 0.560 1010.240 15.850 ;
        RECT 1015.840 0.560 1093.540 15.850 ;
      LAYER Metal3 ;
        RECT 0.560 935.130 1099.440 1099.860 ;
        RECT 21.030 929.530 925.050 935.130 ;
        RECT 0.560 785.130 1099.440 929.530 ;
        RECT 111.030 779.530 1015.050 785.130 ;
        RECT 0.560 635.130 1099.440 779.530 ;
        RECT 21.030 629.530 925.050 635.130 ;
        RECT 0.560 606.780 1099.440 629.530 ;
        RECT 0.560 577.660 1099.140 606.780 ;
        RECT 0.860 570.900 1099.140 577.660 ;
        RECT 0.560 560.860 1099.140 570.900 ;
        RECT 0.860 558.580 1099.140 560.860 ;
        RECT 0.560 553.020 1099.140 558.580 ;
        RECT 0.860 551.860 1099.140 553.020 ;
        RECT 0.560 550.780 1099.140 551.860 ;
        RECT 0.860 547.380 1099.140 550.780 ;
        RECT 0.560 545.180 1099.140 547.380 ;
        RECT 0.860 544.020 1099.140 545.180 ;
        RECT 0.560 539.580 1099.140 544.020 ;
        RECT 0.860 537.300 1099.140 539.580 ;
        RECT 0.560 528.380 1099.140 537.300 ;
        RECT 0.860 527.220 1099.140 528.380 ;
        RECT 0.560 517.180 1099.140 527.220 ;
        RECT 0.860 511.540 1099.140 517.180 ;
        RECT 0.560 508.180 1099.140 511.540 ;
        RECT 0.560 485.130 1099.440 508.180 ;
        RECT 111.030 479.530 1015.050 485.130 ;
        RECT 0.560 335.130 1099.440 479.530 ;
        RECT 21.030 329.530 925.050 335.130 ;
        RECT 0.560 185.130 1099.440 329.530 ;
        RECT 111.030 179.530 1015.050 185.130 ;
        RECT 0.560 35.130 1099.440 179.530 ;
        RECT 21.030 29.530 925.050 35.130 ;
        RECT 0.560 0.140 1099.440 29.530 ;
      LAYER Metal4 ;
        RECT 58.380 0.090 110.240 1099.750 ;
        RECT 115.840 0.090 200.240 1099.750 ;
        RECT 205.840 0.090 290.240 1099.750 ;
        RECT 295.840 0.090 380.240 1099.750 ;
        RECT 385.840 0.090 470.240 1099.750 ;
        RECT 475.840 0.090 560.240 1099.750 ;
        RECT 565.840 0.090 567.140 1099.750 ;
  END
END chip_core
END LIBRARY

